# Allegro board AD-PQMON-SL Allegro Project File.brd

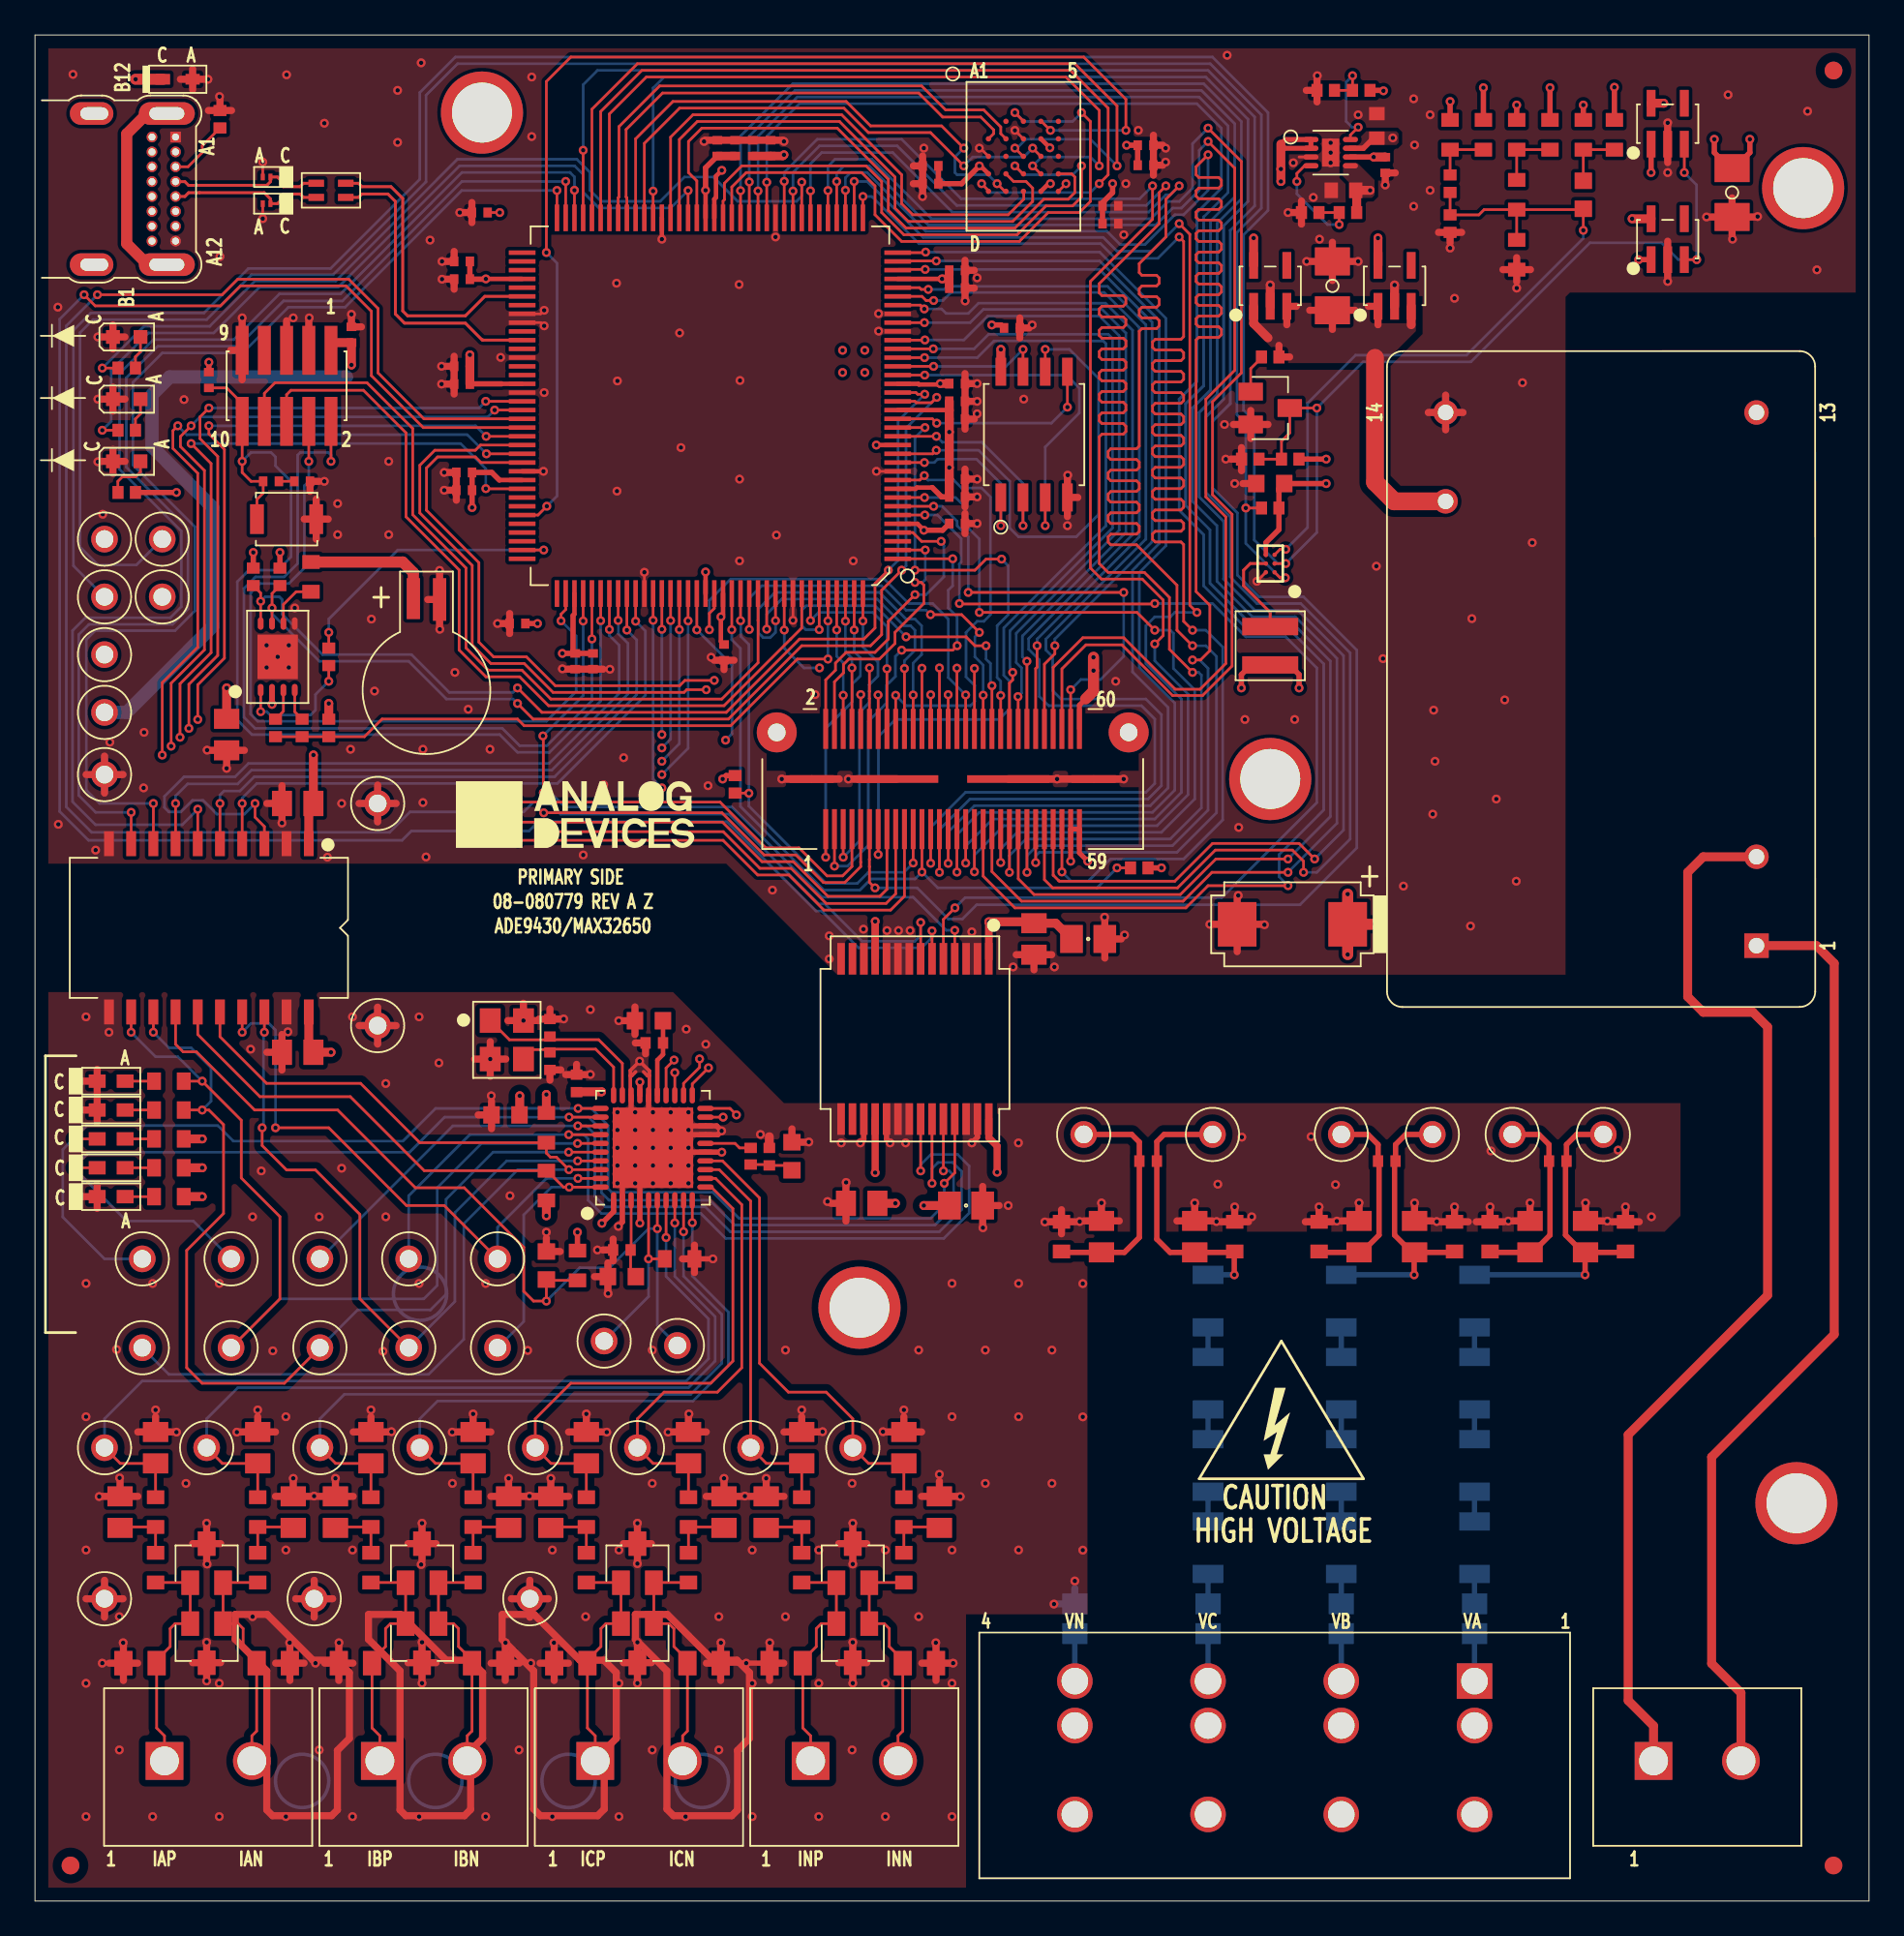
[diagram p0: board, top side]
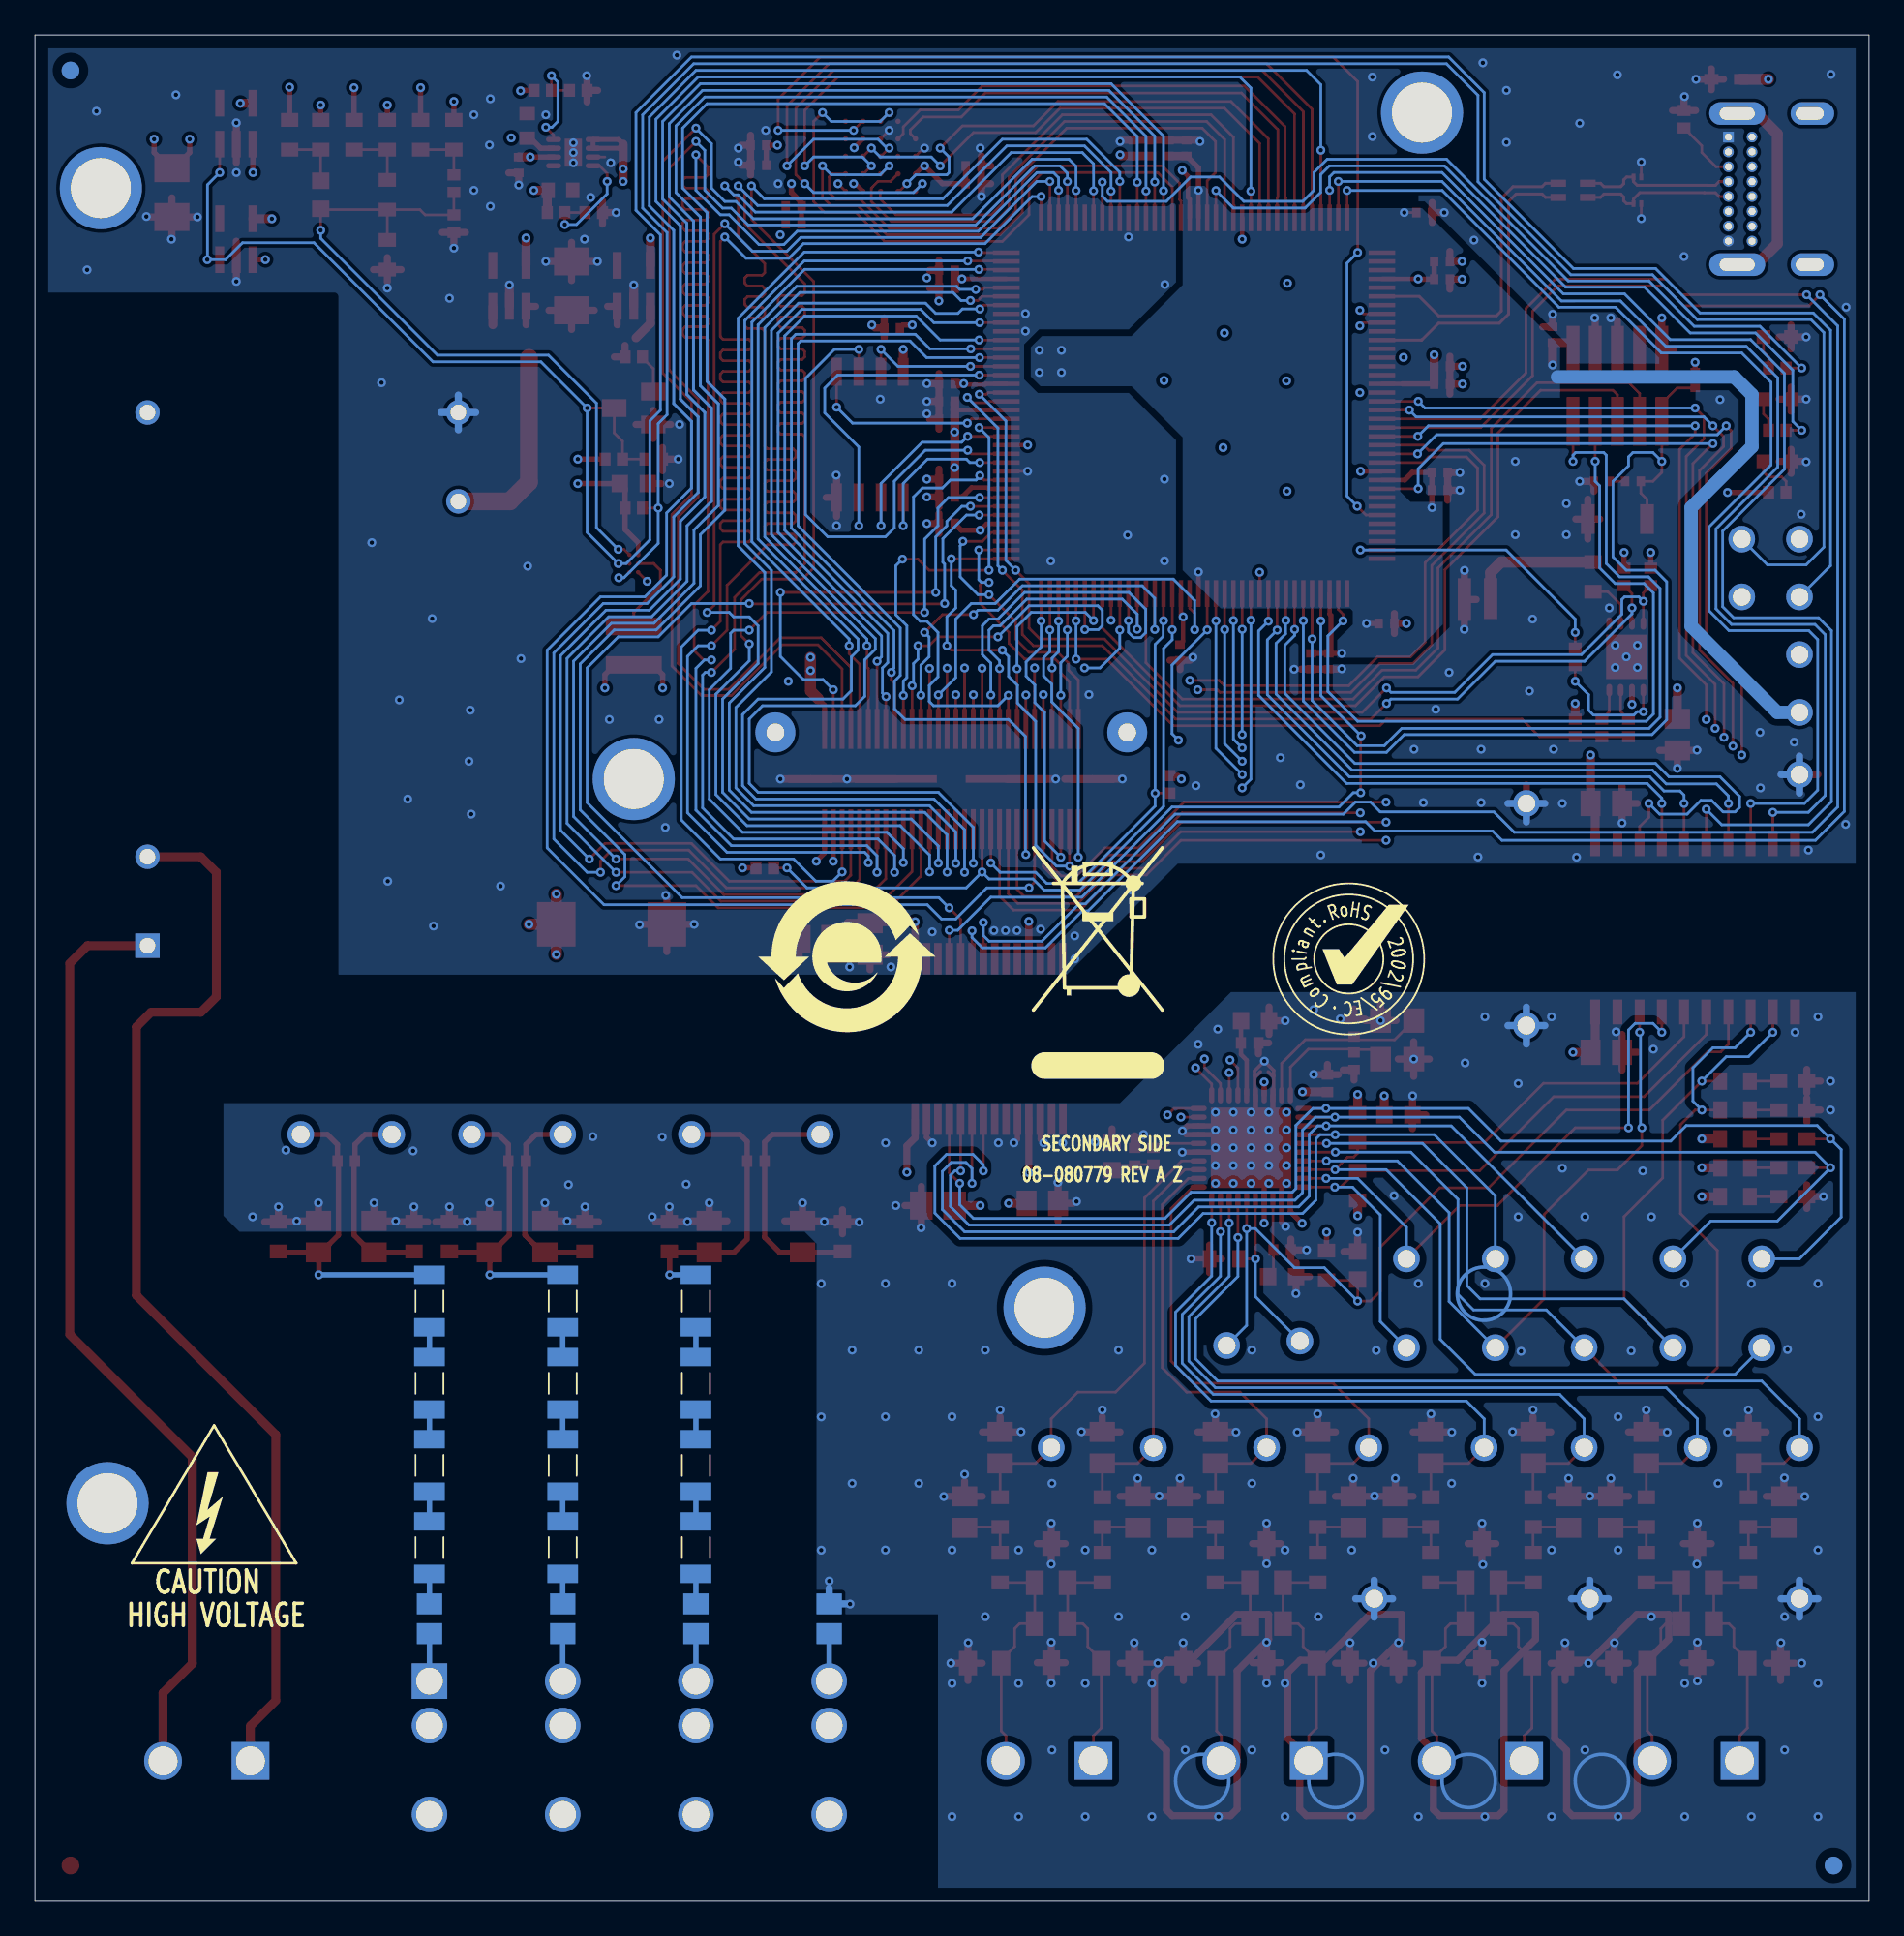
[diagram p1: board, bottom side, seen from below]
Outline 104.9 x 106.68 mm; copper layers: TOP, L2_GND, L3_PWR, BOTTOM. Coordinates in mm from the lower left corner of the outline.
Outline path: 0,106.68 0,0 104.9,0 104.9,106.68 0,106.68

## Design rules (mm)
constraint set DEFAULT: min track width 0.152
net group CLK_CS_MG: nets HYP_CLK HYP_CS0N
net group DP_USB_D_90OHM: nets USB_DN USB_DP
net group DP_USB_DP_CM_90OHM: nets USB_DN_CM USB_DP_CM
net group HYP_CLK: nets HYP_CLKN
net group RESET_CS_MG: nets HYP_RESET
net group SD_CARD: nets SDIO_CLK SDIO_CMD SDIO_DAT0 SDIO_DAT1 SDIO_DAT2 SDIO_DAT3

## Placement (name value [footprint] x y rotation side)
BT1  N/A  [BTMS621FE-FL11E]  22.39 69.22 180 top
C1  0.1uF  [C0805]  10.96 66.68 90 top
C2  0.1uF  [C0805]  57.14 55 90 top
C3  10uF  [C0805H60]  60.24 55 0 top
C4  0.1uF  [C0805]  15.03 62.75 0 top
C5  0.1uF  [C0805]  47.28 39.89 0 top
C6  0.1uF  [C0805]  15.03 48.52 0 top
C7  10uF  [C0805H60]  53.25 39.76 0 top
C8  470UF  [C7343H157]  71.92 55.84 180 top
C9  22uF  [C0603]  70.65 81.03 180 top
C10  22uF  [C1206H71]  74.21 92.34 90 top
C11  33pF  [C0603]  88.56 97.54 270 top
C12  22uF  [C1206H71]  97.07 97.67 270 top
C15  TBD0805  [C0805]  4.87 22.23 90 top
C16  TBD0805  [C0805]  14.77 22.23 270 top
C17  TBD0805  [C0805]  17.19 22.23 90 top
C18  TBD0805  [C0805]  27.09 22.23 270 top
C19  0.022UF  [C0805H55]  19.22 25.92 90 top
C20  0.022UF  [C0805H55]  25.06 25.92 270 top
C21  TBD0805  [C0805]  29.5 22.23 90 top
C22  TBD0805  [C0805]  39.41 22.23 270 top
C23  0.022UF  [C0805H55]  88.69 37.98 90 top
C24  0.022UF  [C0805H55]  31.54 25.92 90 top
C25  0.022UF  [C0805H55]  37.38 25.92 270 top
C26  TBD0805  [C0805]  41.82 22.23 90 top
C27  0.022UF  [C0805H55]  85.51 37.98 90 top
C28  TBD0805  [C0805]  51.73 22.23 270 top
C29  0.022UF  [C0805H55]  6.9 25.92 90 top
C30  0.022UF  [C0805H55]  12.74 25.92 270 top
C31  0.022UF  [C0805H55]  43.86 25.92 90 top
C32  0.022UF  [C0805H55]  49.7 25.92 270 top
C33  0.022UF  [C0805H55]  78.91 37.98 90 top
C34  0.022UF  [C0805H55]  66.33 37.98 90 top
C35  0.022UF  [C0805H55]  75.73 37.98 90 top
C36  0.022UF  [C0805H55]  61 37.98 90 top
C37  18pF  [C0402]  29.45 48.01 270 top
C38  18pF  [C0402]  29.45 49.92 90 top
C39  1uF  [C0603]  29.25 36.33 90 top
C40  4.7uF  [C0603]  26.91 44.94 0 top
C41  4.7uF  [C0603]  43.3 42.58 270 top
C42  4.7uF  [C0603]  35.12 50.33 0 top
C43  4.7uF  [C0603]  33.57 35.7 0 top
C44  0.1uF  [C0402]  30.98 46.74 270 top
C45  0.1uF  [C0402]  42 42.55 270 top
C46  0.1uF  [C0402]  35.42 49.06 0 top
C47  0.1uF  [C0402]  33.57 37.22 0 top
C52  51pF  [C0402]  87.1 42.3 180 top
C54  51pF  [C0402]  77.32 42.3 180 top
C55  51pF  [C0402]  63.67 42.3 180 top
C62  1uF  [C0402]  39.03 100.21 270 top
C63  1uF  [C0402]  25.44 96.53 0 top
C64  1uF  [C0402]  24.55 81.67 0 top
C65  1uF  [C0402]  52.75 92.21 180 top
C66  0.01uF  [C0402]  40.05 100.21 270 top
C67  0.01uF  [C0402]  52.75 86.75 180 top
C68  0.01uF  [C0402]  24.55 80.65 0 top
C69  0.01uF  [C0402]  52.75 93.23 180 top
C70  0.01uF  [C0402]  24.42 92.72 180 top
C71  0.01uF  [C0402]  52.75 85.73 0 top
C72  0.01uF  [C0402]  52.75 81.29 0 top
C73  0.01uF  [C0402]  42.08 100.21 90 top
C74  1uF  [C0402]  52.75 84.72 0 top
C75  1uF  [C0402]  24.42 93.73 180 top
C76  1uF  [C0402]  41.06 100.21 90 top
C77  1uF  [C0402]  52.75 80.27 0 top
C78  1uF  [C0402]  24.42 87.74 180 top
C79  1uF  [C0402]  24.42 86.72 180 top
C80  1uF  [C0402]  52.75 78.75 0 top
C81  1uF  [C0402]  39.41 71.38 270 top
C82  0.01uF  [C0402]  30.9 70.87 270 top
C83  1uF  [C0402]  31.92 70.87 270 top
C84  1uF  [C0402]  51.22 99.2 0 top
C85  0.1UF  [C0402]  51.22 98.18 180 top
C86  0.1UF  [C0402]  61.51 95.89 0 top
C87  1uF  [C0402]  61.51 96.91 0 top
C88  0.1UF  [C0402]  63.52 99.23 180 top
C89  0.1UF  [C0402]  63.52 100.38 180 top
C96  0.1UF  [C0402]  55.88 89.93 0 top
C101  0.1UF  [C0402]  18.1 89.54 90 top
C123  1uF  [C0402]  77.23 99.25 270 top
C124  4.7uF  [C0603#2]  74.84 97.8 180 top
C125  4.7uF  [C0603#2]  76.75 101.48 90 top
C142  1uF  [C0402]  27.6 73.03 180 top
C180  0.1UF  [C0402]  13.5 81.16 180 top
D6  SESD0201X1UN-0020-09  [D0201]  13.25 98.56 180 top
D7  SESD0201X1UN-0020-09  [D0201]  13.25 97.04 180 top
D10  1N4148X-TP  [SOD523_B]  8.17 104.15 0 top
DS1  LG L29K-G2J1-24-Z  [LED0603-2]  5.25 82.3 0 top
DS2  LG L29K-G2J1-24-Z  [LED0603-2]  5.25 85.86 0 top
DS3  LG L29K-G2J1-24-Z  [LED0603-2]  5.25 89.42 0 top
FB1  120OHM  [L0402]  40.93 42.58 90 top
L1  1500 OHMS  [L0805]  82.34 16.14 90 bottom
L2  1500 OHMS  [L0805]  74.72 16.14 90 bottom
L3  1500 OHMS  [L0805]  67.1 16.14 90 bottom
L4  1500 OHMS  [L0805]  59.48 16.14 90 bottom
L5  1.2UH  [LSMSQ110H118]  70.65 71.76 270 top
L7  90OHMS AT 100MEGHZ  [L0805-4PH39]  16.93 97.8 180 top
LED1  APT1608LSECK/J3-PRV  [LED0603]  4.36 43.57 0 top
LED2  APT1608LSECK/J3-PRV  [LED0603]  4.36 46.87 0 top
LED3  APT1608LSECK/J3-PRV  [LED0603]  4.36 45.22 0 top
LED5  APT1608LZGCK  [LED0603]  4.36 40.27 0 top
LED6  APT1608LSECK/J3-PRV  [LED0603]  4.36 41.92 0 top
M1  IRM-03-3.3  [MIRM-03]  98.47 54.62 90 top
NOREF  -  [unnamed]  102.87 2.03 0 top
NOREF#2  -  [#2]  52.31 134.86 0 top
NOREF#3  -  [#2]  -50.76 -152.01 0 top
NOREF#4  -  [#2]  7.41 8.01 0 top
NOREF#5  -  [#2]  206.9 9.22 0 top
NOREF#6  -  [#2]  220.51 -1.26 0 top
NOREF#7  -  [#2]  -50.76 -152.01 0 top
NOREF#8  -  [unnamed]  102.87 104.65 0 top
NOREF#9  -  [#2]  -50.76 -152.01 0 top
NOREF#10  -  [#2]  104.9 0 90 top
NOREF#11  -  [unnamed]  100.75 22.74 0 top
NOREF#12  -  [#2]  104.9 0 90 top
NOREF#13  -  [#2]  20.61 -29.71 0 top
NOREF#14  -  [#2]  6.14 15.11 90 top
NOREF#15  -  [#2]  71.03 26.93 0 top
NOREF#16  -  [#2]  52.45 53.34 0 top
NOREF#17  -  [#2]  0 0 0 top
NOREF#18  -  [#2]  104.9 106.68 180 top
NOREF#19  -  [#2]  177.18 229.35 0 top
NOREF#20  -  [#2]  0 0 0 top
NOREF#21  -  [#2]  224.68 7.78 0 top
NOREF#22  -  [#2]  0 106.68 0 top
NOREF#23  -  [#2]  14.49 100.36 0 top
NOREF#24  -  [unnamed]  101.13 97.93 0 top
NOREF#25  -  [unnamed]  70.65 64.14 0 top
NOREF#26  -  [unnamed]  47.16 33.92 0 top
NOREF#27  -  [unnamed]  25.57 102.24 0 top
NOREF#28  -  [#2]  104.9 0 0 top
NOREF#29  -  [#2]  0 0 0 top
NOREF#30  -  [#2]  0 106.68 0 top
NOREF#31  -  [#2]  229.22 120.79 0 top
NOREF#32  -  [#2]  0 106.68 270 top
NOREF#33  -  [#2]  51.73 4.15 270 top
NOREF#34  -  [#2]  30.77 62.11 0 top
NOREF#35  -  [#2]  131.44 363.85 0 top
NOREF#36  -  [#2]  7.41 8.01 0 top
NOREF#37  -  [unnamed]  2.03 2.03 0 top
NOREF#38  -  [#2]  29.76 53.86 180 bottom
NOREF#39  -  [#2]  58.46 53.98 180 bottom
NOREF#40  -  [unnamed]  2.03 2.03 180 bottom
NOREF#41  -  [#2]  34.84 63.89 180 bottom
NOREF#42  -  [unnamed]  102.87 104.65 180 bottom
NOREF#43  -  [#2]  94.91 22.11 180 bottom
P1  FTSH-105-01-L-DV-K  [CNHDR2X5H245]  14.39 86.62 180 top
P2  QSH-030-01-L-D-A  [CNHDR2X30H202]  52.49 64.14 0 top
P3  TBP04R2-500-02BE  [CNCUITBP04R2-500-02]  7.41 8.01 0 top
P4  TBP04R2-500-02BE  [CNCUITBP04R2-500-02]  19.73 8.01 0 top
P5  TBP04R2-500-02BE  [CNCUITBP04R2-500-02]  32.04 8.01 0 top
P6  TBP04R2-500-02BE  [CNCUITBP04R2-500-02]  44.36 8.01 0 top
P7  TBP04R2-500-02BE  [CNCUITBP04R2-500-02]  92.58 8.01 0 top
P8  1720592  [CNPHOENIX1720592]  82.34 12.57 180 top
P10  2137160001  [CNMOLEX2137160001]  8.04 100.85 270 top
Q1  MMBD4148SE  [SOT23]  9.82 19.31 0 top
Q2  MMBD4148SE  [SOT23]  9.82 14.74 180 top
Q3  MMBD4148SE  [SOT23]  22.14 19.31 0 top
Q4  MMBD4148SE  [SOT23]  22.14 14.74 180 top
Q5  MMBD4148SE  [SOT23]  34.46 19.31 0 top
Q6  MMBD4148SE  [SOT23]  34.46 14.74 180 top
Q7  MMBD4148SE  [SOT23]  46.78 19.31 0 top
Q8  BSS138LT1G  [SOT23]  70.65 85.35 270 top
Q9  MMBD4148SE  [SOT23]  46.78 14.74 180 top
R1  5.1  [R0805]  6.01 13.6 180 top
R2  5.1  [R0805]  13.63 13.6 180 top
R3  5.1  [R0805]  18.33 13.6 180 top
R4  5.1  [R0805]  25.95 13.6 180 top
R5  0  [R0603]  19.22 19.06 90 top
R6  0  [R0603]  25.06 19.06 90 top
R7  1K  [R0603]  19.22 22.23 90 top
R8  1K  [R0603]  25.06 22.23 90 top
R9  249K  [R1206]  82.34 20.2 90 bottom
R10  5.1  [R0805]  30.65 13.6 180 top
R11  5.1  [R0805]  38.27 13.6 180 top
R12  249K  [R1206]  74.72 20.2 90 bottom
R13  249K  [R1206]  67.1 20.2 90 bottom
R14  0  [R0603]  31.54 19.06 90 top
R15  0  [R0603]  37.38 19.06 90 top
R16  1K  [R0603]  31.54 22.23 90 top
R17  1K  [R0603]  37.38 22.23 90 top
R18  249K  [R1206]  82.34 24.9 90 bottom
R19  5.1  [R0805]  42.97 13.6 180 top
R20  5.1  [R0805]  50.59 13.6 180 top
R21  0  [R0603]  6.9 19.06 90 top
R22  0  [R0603]  12.74 19.06 90 top
R23  0  [R0603]  43.86 19.06 90 top
R24  0  [R0603]  49.7 19.06 90 top
R25  1K  [R0603]  43.86 22.23 90 top
R26  1K  [R0603]  49.7 22.23 90 top
R27  249K  [R1206]  74.72 24.9 90 bottom
R28  249K  [R1206]  67.1 24.9 90 bottom
R29  1K  [R0603]  90.97 37.98 90 top
R30  249K  [R1206]  82.34 29.6 90 bottom
R31  249K  [R1206]  74.72 29.6 90 bottom
R32  1K  [R0603]  81.19 37.98 90 top
R33  1K  [R0603]  83.23 37.98 90 top
R34  249K  [R1206]  67.1 29.6 90 bottom
R35  1K  [R0603]  6.9 22.23 90 top
R36  1K  [R0603]  12.74 22.23 90 top
R37  249K  [R1206]  82.34 34.3 90 bottom
R38  249K  [R1206]  74.72 34.3 90 bottom
R39  249K  [R1206]  67.1 34.3 90 bottom
R40  1K  [R0603]  68.62 37.98 90 top
R41  1K  [R0603]  73.45 37.98 90 top
R42  1K  [R0603]  58.71 37.98 90 top
R43  10K  [R0603]  31.03 36.33 90 top
R44  1K  [R0603]  7.66 43.57 0 top
R45  1K  [R0603]  7.66 41.92 0 top
R46  1K  [R0603]  7.66 46.87 0 top
R47  1K  [R0603]  7.66 45.22 0 top
R48  28K  [R0402]  75.86 103.51 180 top
R49  23.2K  [R0402]  73.83 103.51 180 top
R50  1K  [R0603]  7.66 40.27 0 top
R51  115K  [R0402]  75.1 96.53 180 top
R52  44.2K  [R0402]  72.94 96.53 180 top
R53  4.7K  [R0402]  40.05 63.84 270 top
R54  10K  [R0603]  29.25 40.9 270 top
R55  4.7K  [R0402]  63.16 59.06 180 top
R56  620  [R0603]  15.79 75.7 90 top
R57  4.7K  [R0402]  12.49 75.7 270 top
R58  0  [R0402]  16.8 71.13 90 top
R59  0  [R0402]  15.28 67.06 270 top
R60  0  [R0402]  13.76 67.06 270 top
R61  4.7K  [R0402]  14.01 75.7 270 top
R62  4.7K  [R0402]  16.8 67.06 270 top
R63  10K  [R0402]  70.65 88.27 180 top
R64  100K  [R0402]  70.65 79.64 180 top
R65  47K  [R0402]  71.8 82.43 180 top
R66  47K  [R0402]  69.51 82.43 180 top
R67  0  [R0603]  80.94 100.97 270 top
R68  0  [R0603]  82.84 100.97 270 top
R69  20K  [R0402]  80.94 98.18 270 top
R70  3.57K  [R0402]  80.94 95.89 270 top
R71  0  [R0603]  84.75 100.97 270 top
R72  0  [R0603]  86.65 100.97 270 top
R73  100K  [R0603]  84.75 97.54 270 top
R74  100K  [R0603]  84.75 94.12 270 top
R75  0  [R0603]  88.56 100.97 270 top
R76  0  [R0603]  90.34 100.97 270 top
R77  866  [R0402]  5.25 80.53 180 top
R78  866  [R0402]  5.25 84.08 0 top
R79  866  [R0402]  5.25 87.64 0 top
R81  10K  [R0603]  36.87 36.71 180 top
R96  10K  [R0603]  29.25 44.2 90 top
R125  10K  [R0402]  9.95 86.95 270 top
R126  10  [R0402]  15.28 81.16 0 top
R157  5.1K  [R0402]  10.58 101.86 270 top
S1  B3U-1000P  [SWSML118W98H69]  14.39 79 0 top
TP1  WHT  [CNKEY5001TP]  21.38 31.63 0 top
TP2  WHT  [CNKEY5001TP]  26.46 36.71 0 top
TP3  WHT  [CNKEY5001TP]  6.14 31.63 0 top
TP4  WHT  [CNKEY5001TP]  26.46 31.63 0 top
TP5  WHT  [CNKEY5001TP]  16.3 36.71 0 top
TP6  WHT  [CNKEY5001TP]  36.74 31.76 0 top
TP7  WHT  [CNKEY5001TP]  11.22 31.63 0 top
TP8  WHT  [CNKEY5001TP]  11.22 36.71 0 top
TP9  WHT  [CNKEY5001TP]  16.3 31.63 0 top
TP10  WHT  [CNKEY5001TP]  6.14 36.71 0 top
TP11  WHT  [CNKEY5001TP]  3.98 77.86 0 top
TP12  WHT  [CNKEY5001TP]  7.28 77.86 0 top
TP13  WHT  [CNKEY5001TP]  3.98 67.95 0 top
TP14  WHT  [CNKEY5001TP]  3.98 64.4 180 top
TP15  WHT  [CNKEY5001TP]  3.98 71.26 0 top
TP16  WHT  [CNKEY5001TP]  19.6 62.75 0 top
TP17  WHT  [CNKEY5001TP]  3.98 74.56 0 top
TP18  WHT  [CNKEY5001TP]  7.28 74.56 0 top
TP21  WHT  [CNKEY5001TP]  19.6 50.05 0 top
TP22  WHT  [CNKEY5001TP]  3.98 17.28 0 top
TP25  WHT  [CNKEY5001TP]  22.01 25.92 0 top
TP26  WHT  [CNKEY5001TP]  16.3 25.92 0 top
TP27  WHT  [CNKEY5001TP]  28.3 17.28 0 top
TP28  WHT  [CNKEY5001TP]  15.97 17.28 0 top
TP29  WHT  [CNKEY5001TP]  34.46 25.92 0 top
TP30  WHT  [CNKEY5001TP]  28.62 25.92 0 top
TP39  WHT  [CNKEY5001TP]  46.78 25.92 0 top
TP41  WHT  [CNKEY5001TP]  40.93 25.92 0 top
TP43  WHT  [CNKEY5001TP]  9.82 25.92 0 top
TP45  WHT  [CNKEY5001TP]  3.98 25.92 0 top
TP47  WHT  [CNKEY5001TP]  21.38 36.71 0 top
TP49  WHT  [CNKEY5001TP]  32.55 32.01 0 top
TP53  WHT  [CNKEY5001TP]  67.35 43.82 180 top
TP54  WHT  [CNKEY5001TP]  59.98 43.82 180 top
TP55  WHT  [CNKEY5001TP]  79.92 43.82 180 top
TP56  WHT  [CNKEY5001TP]  74.72 43.82 180 top
TP57  WHT  [CNKEY5001TP]  89.7 43.82 180 top
TP58  WHT  [CNKEY5001TP]  84.5 43.82 180 top
U1  ADE9430ACPZ  [QFN40_6X6_PAD4_6X4_6]  35.35 43.06 0 top
U2  MAX32650GCE+  [QFP144-4]  38.61 85.49 90 top
U3  MAX31343ETAY+T  [DFN8_3X4_PAD2_3X2_7]  13.88 71.13 0 top
U4  ADUM6424ABRNZ3  [SO28]  50.33 49.28 180 top
U5  ADUM4152BRIZ  [SO20WBH104]  9.95 55.63 180 top
U6  LTC3306  [WLCSP6H26]  70.65 76.46 90 top
U7  MAX40203AUK+  [SOT23-5L]  77.76 92.34 0 top
U8  MAX40203AUK+  [SOT23-5L]  70.65 92.34 0 top
U9  MAX40203AUK+  [SOT23-5L]  93.39 101.61 0 top
U10  S80KS5122GABHM020  [BGA24_8X6]  56.54 99.74 270 top
U11  MX25U6432FM2I02  [SOP8_A]  57.15 83.83 0 top
U12  MAX40203AUK+  [SOT23-5L]  93.39 95 0 top
U17  ADP225ACPZ  [QFN8_2X2_PAD1_6X1]  74.11 99.95 270 top
X2  24.576MEGHZ  [YSML126W98H31]  26.99 49.23 270 top

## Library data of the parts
BT1 = BAT: User Part Number: UPN; alternate symbols: (BTMS621FE-FL11E); part number: BAT_SM-N/A,3V,E017113,BTMS621FE-FL11E
C1 C2 C4-C6 = CAP: User Part Number: UPN; Tolerance: 5; alternate symbols: (C0805); part number: CAP_SM-0.1UF,50V,5,E031467,C0805; tolerance: 5
C3 C7 = CAP: Tolerance: 10; User Part Number: UPN; alternate symbols: (C0805H60); part number: CAP_SM-10UF,25V,10,E014704,C0805H60; tolerance: 10
C8 = CAPP: Tolerance: 20; User Part Number: UPN; alternate symbols: (C7343H157); part number: CAPP_SM-470UF,6.3V,20,E046064,C7343H157; tolerance: 20
C9 = CAP: User Part Number: UPN; Tolerance: 20; alternate symbols: (C0603); part number: CAP_SM-22UF,6.3V,20,E021512,C0603; tolerance: 20
C10 C12 = CAP: Tolerance: 20; User Part Number: UPN; alternate symbols: (C1206H71); part number: CAP_SM-22UF,6.3V,20,E042072,C1206H71; tolerance: 20
C11 = CAP: User Part Number: UPN; Tolerance: 5; alternate symbols: (C0603); part number: CAP_SM-33PF,50V,5,E000396,C0603; tolerance: 5
C15-C18 C21 C22 C26 C28 = CAP: User Part Number: UPN; alternate symbols: (C0805); part number: CAP_SM-TBD0805,TBD0805,TBD0805,E000383,C0805
C19 C20 C23-C25 C27 C29-C36 = CAP: User Part Number: UPN; Tolerance: 5; alternate symbols: (C0805H55); part number: CAP_SM-0.022UF,50V,5,E047690,C0805H55; tolerance: 5
C37 C38 = CAP: User Part Number: UPN; Tolerance: 5; alternate symbols: (C0402); part number: CAP_SM-18PF,50V,5,E007476,C0402; tolerance: 5
C39 = CAP: User Part Number: UPN; Tolerance: 10; alternate symbols: (C0603); part number: CAP_SM-1UF,16V,10,E020596,C0603; tolerance: 10
C40-C43 = CAP: User Part Number: UPN; Tolerance: 10; alternate symbols: (C0603); part number: CAP_SM-4.7UF,10V,10,E025322,C0603; tolerance: 10
C44-C47 = CAP: User Part Number: UPN; Tolerance: 10; alternate symbols: (C0402); part number: CAP_SM-0.1UF,25V,10,E025708,C0402; tolerance: 10
C52 C54 C55 = CAP: User Part Number: UPN; Tolerance: 5; alternate symbols: (C0402); part number: CAP_SM-51PF,50V,5,E029660,C0402; tolerance: 5
C62-C65 C74-C81 C83 C84 C87 C123 C142 = CAP: User Part Number: UPN; Tolerance: 10; alternate symbols: (C0402L); part number: CAP_SM-1UF,16V,10,E019219,C0402; tolerance: 10
C66-C73 C82 = CAP: User Part Number: UPN; Tolerance: 10; alternate symbols: (C0402L); part number: CAP_SM-0.01UF,100V,10,E032295,C0402; tolerance: 10
C85 C86 C88 C89 C96 C101 C180 = CAP: User Part Number: UPN; Tolerance: 10; alternate symbols: (C0402L); part number: CAP_SM-0.1UF,50V,10,E048331,C0402; tolerance: 10
C124 C125 = CAP: User Part Number: UPN; Tolerance: 10; alternate symbols: (C0603L); part number: CAP_SM-4.7UF,10V,10,E030749,C0603; tolerance: 10
D6 D7 = DIO: Tolerance: N/A; User Part Number: UPN; alternate symbols: (D0201); part number: DIO_SM-SESD0201X1UN-0020-09,9V,N/A,E022225,D0201; tolerance: N/A
D10 = DIO: Tolerance: N/A; User Part Number: UPN; alternate symbols: (SOD523_B); part number: DIO_SM-1N4148X-TP,75V,N/A,E039538,SOD523_B; tolerance: N/A
DS1-DS3 = DIOLED: Tolerance: N/A; User Part Number: UPN; alternate symbols: (LED0603-2); part number: DIOLED_SM-LG L29K-G2J1-24-Z,N/A,N/A,E010948,LED0603-2; tolerance: N/A
FB1 = FERRITE: User Part Number: UPN; Tolerance: 25; alternate symbols: (L0402); part number: FERRITE_SM-120OHM,25,E038542,L0402; tolerance: 25
L1-L4 = FERRITE: User Part Number: UPN; Tolerance: 25; alternate symbols: (L0805); part number: FERRITE_SM-1500 OHMS,25,E008092,L0805; tolerance: 25
L5 = IND_V10: Tolerance: 20; User Part Number: UPN; alternate symbols: (LSMSQ110H118); part number: IND_V10_SM-1.2UH,20,E061966,LSMSQ110H118; tolerance: 20
L7 = CHOKE4P: User Part Number: UPN; Tolerance: 25; alternate symbols: (L0805-4PH39); part number: CHOKE4P_SM-90OHMS AT 100MEGHZ,25,E027226,L0805-4PH39; tolerance: 25
LED1-LED3 LED6 = DIOLED: Tolerance: N/A; User Part Number: UPN; alternate symbols: (LED0603); part number: DIOLED_SM-APT1608LSECK/J3-PRV,1.8V,N/A,E030191,LED0603; tolerance: N/A
LED5 = DIOLED: Tolerance: N/A; User Part Number: UPN; alternate symbols: (LED0603); part number: DIOLED_SM-APT1608LZGCK,2.65V,N/A,E027397,LED0603; tolerance: N/A
M1 = MODIRM_03: User Part Number: UPN; Tolerance: N/A; alternate symbols: (MIRM-03); part number: MODIRM_03_TH-IRM-03-3.3,E064109,MIRM-03; tolerance: N/A
P1 = CN10P_ODD_EVEN: Tolerance: N/A; User Part Number: UPN; alternate symbols: (CNHDR2X5H245); part number: CN10P_ODD_EVEN_SM-FTSH-105-01-L-DV-K,E023407,CNHDR2X5H245; tolerance: N/A
P2 = CN60P_ODD_EVEN_4GND: User Part Number: UPN; Tolerance: N/A; alternate symbols: (CNHDR2X30H202); part number: CN60P_ODD_EVEN_4GND_SM-QSH-030-01-L-D-A,E014016,CNHDR2X30H202; tolerance: N/A
P3-P7 = CN2P: User Part Number: UPN; Tolerance: N/A; alternate symbols: (CNCUITBP04R2-500-02); part number: CN2P_TH-TBP04R2-500-02BE,E060556,CNCUITBP04R2-500-02; tolerance: N/A
P8 = CN4P_ABC: User Part Number: UPN; Tolerance: N/A; alternate symbols: (CNPHOENIX1720592); part number: CN4P_ABC_TH-1720592,E054826,CNPHOENIX1720592; tolerance: N/A
P10 = CN16PAB_4GND: Tolerance: N/A; User Part Number: UPN; alternate symbols: (CNMOLEX2137160001); part number: CN16PAB_4GND_TH-2137160001,E052752,CNMOLEX2137160001; tolerance: N/A
Q1-Q7 Q9 = DIOBAV99LT1: User Part Number: UPN; Tolerance: N/A; alternate symbols: (SOT23); part number: DIOBAV99LT1_SM-MMBD4148SE,100V,N/A,E007870,SOT23; tolerance: N/A
Q8 = TRANNMOSFET_V8: User Part Number: UPN; Tolerance: N/A; alternate symbols: (SOT23); part number: TRANNMOSFET_V8_SM-BSS138LT1G,E018770,SOT23; tolerance: N/A
R1-R4 R10 R11 R19 R20 = RES: User Part Number: UPN; Tolerance: 5; alternate symbols: (R0805); part number: RES_SM-5.1,E014529,1/8W,5,R0805; tolerance: 5
R5 R6 R14 R15 R21-R24 = RESJMPRSHRT: User Part Number: UPN; Tolerance: JUMPER; alternate symbols: (R0603); part number: RESJMPRSHRT_SM-0,E004447,1/10W,JUMPER,R0603; tolerance: JUMPER
R7 R8 R16 R17 R25 R26 R29 R32 R33 R35 R36 R40-R42 R44-R47 R50 = RES: User Part Number: UPN; Tolerance: 0.1; alternate symbols: (R0603); part number: RES_SM-1K,E020747,1/10W,0.1,R0603; tolerance: 0.1
R9 R12 R13 R18 R27 R28 R30 R31 R34 R37-R39 = RES: User Part Number: UPN; Tolerance: 0.1; alternate symbols: (R1206); part number: RES_SM-249K,E015146,1/4W,0.1,R1206; tolerance: 0.1
R43 R54 R81 R96 = RES: User Part Number: UPN; Tolerance: 5; alternate symbols: (R0603); part number: RES_SM-10K,E028377,1/10W,5,R0603; tolerance: 5
R48 = RES: User Part Number: UPN; Tolerance: 1; alternate symbols: (R0402); part number: RES_SM-28K,E010020,1/10W,1,R0402; tolerance: 1
R49 = RES: User Part Number: UPN; Tolerance: 1; alternate symbols: (R0402); part number: RES_SM-23.2K,E036030,1/10W,1,R0402; tolerance: 1
R51 = RES: User Part Number: UPN; Tolerance: 1; alternate symbols: (R0402); part number: RES_SM-115K,E025179,1/10W,1,R0402; tolerance: 1
R52 = RES: User Part Number: UPN; Tolerance: 1; alternate symbols: (R0402); part number: RES_SM-44.2K,E023712,1/10W,1,R0402; tolerance: 1
R53 R55 R57 R61 R62 = RES: User Part Number: UPN; Tolerance: 5; alternate symbols: (R0402); part number: RES_SM-4.7K,E048466,1/16W,5,R0402; tolerance: 5
R56 = RES: User Part Number: UPN; Tolerance: 1; alternate symbols: (R0603); part number: RES_SM-620,E033969,1/10W,1,R0603; tolerance: 1
R58-R60 = RES: User Part Number: UPN; Tolerance: JUMPER; alternate symbols: (R0402); part number: RES_SM-0,E003438,1/10W,JUMPER,R0402; tolerance: JUMPER
R63 = RES: User Part Number: UPN; Tolerance: 1; alternate symbols: (R0402); part number: RES_SM-10K,E060779,1/16W,1,R0402; tolerance: 1
R64 = RES: User Part Number: UPN; Tolerance: 5; alternate symbols: (R0402); part number: RES_SM-100K,E027220,1/16W,5,R0402; tolerance: 5
R65 R66 = RES: User Part Number: UPN; Tolerance: 0.5; alternate symbols: (R0402); part number: RES_SM-47K,E031653,1/16W,0.5,R0402; tolerance: 0.5
R67 R68 R71 R72 R75 R76 = RES: User Part Number: UPN; Tolerance: JUMPER; alternate symbols: (R0603); part number: RES_SM-0,E034483,1/10W,JUMPER,R0603; tolerance: JUMPER
R69 = RES: User Part Number: UPN; Tolerance: 1; alternate symbols: (R0402); part number: RES_SM-20K,E061761,1/16W,1,R0402; tolerance: 1
R70 = RES: User Part Number: UPN; Tolerance: 1; alternate symbols: (R0402); part number: RES_SM-3.57K,E007344,1/10W,1,R0402; tolerance: 1
R73 R74 = RES: User Part Number: UPN; Tolerance: 0.5; alternate symbols: (R0603); part number: RES_SM-100K,E012705,1/10W,0.5,R0603; tolerance: 0.5
R77-R79 = RES: User Part Number: UPN; Tolerance: 1; alternate symbols: (R0402); part number: RES_SM-866,E015598,1/10W,1,R0402; tolerance: 1
R125 = RES: User Part Number: UPN; Tolerance: 1; alternate symbols: (R0402L); part number: RES_SM-10K,E003751,1/10W,1,R0402; tolerance: 1
R126 = RES: User Part Number: UPN; Tolerance: 1; alternate symbols: (R0402L); part number: RES_SM-10,E003768,1/10W,1,R0402; tolerance: 1
R157 = RES: User Part Number: UPN; Tolerance: 0.1; alternate symbols: (R0402); part number: RES_SM-5.1K,E010267,1/16W,0.1,R0402; tolerance: 0.1
S1 = SWSPST2PIN_V2: Tolerance: N/A; User Part Number: UPN; alternate symbols: (SWSML118W98H69); part number: SWSPST2PIN_V2_SM-B3U-1000P,E016303,SWSML118W98H69; tolerance: N/A
TP1-TP18 TP21 TP22 TP25-TP30 TP39 TP41 TP43 TP45 TP47 TP49 TP53-TP58 = CNTP1P: Tolerance: N/A; User Part Number: UPN; alternate symbols: (CNKEY5001TP); part number: CNTP1P_TH-WHT,E006153,CNKEY5001TP; tolerance: N/A
U1 = ADE9430: User Part Number: UPN; Tolerance: N/A; alternate symbols: (QFN40_6X6_PAD4_6X4_6); part number: ADE9430_SM-ADE9430ACPZ,E050046,QFN40_6X6_PAD4_6X4_6; tolerance: N/A
U2 = ADMAX3265X: Tolerance: N/A; User Part Number: UPN; alternate symbols: (QFP144-4); part number: ADMAX3265X_SM-MAX32650GCE+,E058988,QFP144-4; tolerance: N/A
U3 = ADMAX31343: User Part Number: UPN; Tolerance: N/A; alternate symbols: (DFN8_3X4_PAD2_3X2_7); part number: ADMAX31343_SM-MAX31343ETAY+T,E059805,DFN8_3X4_PAD2_3X2_7; tolerance: N/A
U4 = ADUM6424A: User Part Number: UPN; Tolerance: N/A; alternate symbols: (SO28); part number: ADUM6424A_SM-ADUM6424ABRNZ3,E064108,SO28; tolerance: N/A
U5 = ADUM4152: Tolerance: N/A; User Part Number: UPN; alternate symbols: (SO20WBH104); part number: ADUM4152_SM-ADUM4152BRIZ,E033349,SO20WBH104; tolerance: N/A
U6 = ADLTC3306: Tolerance: N/A; User Part Number: UPN; alternate symbols: (WLCSP6H26); part number: ADLTC3306_SM-LTC3306,E041728,WLCSP6H26; tolerance: N/A
U7-U9 U12 = ADMAX40203: User Part Number: UPN; Tolerance: N/A; alternate symbols: (SOT23-5L); part number: ADMAX40203_SM-MAX40203AUK+,E059461,SOT23-5L; tolerance: N/A
U10 = ICS80KS5122: Tolerance: N/A; User Part Number: UPN; alternate symbols: (BGA24_8X6_PB); part number: ICS80KS5122_SM-S80KS5122GABHM020,E060311,BGA24_8X6; tolerance: N/A
U11 = ICMX25U6432F_V2: User Part Number: UPN; Tolerance: N/A; alternate symbols: (SOP8_A); part number: ICMX25U6432F_V2_SM-MX25U6432FM2I02,E060310,SOP8_A; tolerance: N/A
U17 = ADP22X: User Part Number: UPN; Tolerance: N/A; alternate symbols: (QFN8_2X2_PAD1_6X1); part number: ADP22X_SM-ADP225ACPZ,E016555,QFN8_2X2_PAD1_6X1; tolerance: N/A
X2 = XTAL4PIN_V5: Tolerance: +/-20PPM; User Part Number: UPN; alternate symbols: (YSML126W98H31); part number: XTAL4PIN_V5_SM-24.576MEGHZ,E041028,YSML126W98H31; tolerance: +/-20PPM

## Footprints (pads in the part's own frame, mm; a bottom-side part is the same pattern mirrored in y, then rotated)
BGA24_8X6
  round 0.305 smd: A2(-2,-1) A3(-2,0) A4(-2,1) A5(-2,2) B1(-1,-2) B2(-1,-1) B3(-1,0) B4(-1,1) B5(-1,2) C1(0,-2) C2(0,-1) C3(0,0) C4(0,1) C5(0,2) D1(1,-2) D2(1,-1) D3(1,0) D4(1,1) D5(1,2) E1(2,-2) E2(2,-1) E3(2,0) E4(2,1) E5(2,2)
BTMS621FE-FL11E
  rect 0.762x2.438 smd: N(-0.75,-5.181)
  rect 0.762x2.337 smd: P(0.75,-5.232)
C0402
  rect 0.483x0.559 smd: 1(-0.45,0) 2(0.45,0)
C0603
  rect 0.94x0.991 smd: 1(-0.8,0) 2(0.8,0)
C0603#2
  rect 0.762x0.889 smd: 1(-0.7,0) 2(0.7,0)
C0805
  rect 1.143x1.448 smd: 1(-0.9,0) 2(0.9,0)
C0805H55
  rect 1.143x1.448 smd: 1(-0.9,0) 2(0.9,0)
C0805H60
  rect 1.295x1.6 smd: 1(-0.953,0) 2(0.953,0)
C1206H71
  rect 1.6x2.007 smd: 1(-1.397,0) 2(1.397,0)
C7343H157
  rect 2.21x2.54 smd: N(3.16,0) P(-3.16,0)
CNCUITBP04R2-500-02
  rect 2.159x2.159 hole 1.651: 1(0,0)
  round 2.159 hole 1.651: 2(5,0)
CNHDR2X5H245
  rect 0.737x2.794 smd: 1(-2.54,-2.032) 2(-2.54,2.032) 3(-1.27,-2.032) 4(-1.27,2.032) 5(0,-2.032) 6(0,2.032) 7(1.27,-2.032) 8(1.27,2.032) 9(2.54,-2.032) 10(2.54,2.032)
CNHDR2X30H202
  round 2.286 hole 1.016 unplated: (-10.063,2.667) (10.063,2.667)
  rect 0.279x2.286 smd: 1(-7.264,-2.865) 2(-7.264,2.865) 3(-6.764,-2.865) 4(-6.764,2.865) 5(-6.264,-2.865) 6(-6.264,2.865) 7(-5.763,-2.865) 8(-5.763,2.865) 9(-5.263,-2.865) 10(-5.263,2.865) 11(-4.763,-2.865) 12(-4.763,2.865) 13(-4.262,-2.865) 14(-4.262,2.865) 15(-3.762,-2.865) 16(-3.762,2.865) 17(-3.261,-2.865) 18(-3.261,2.865) 19(-2.761,-2.865) 20(-2.761,2.865) 21(-2.261,-2.865) 22(-2.261,2.865) 23(-1.76,-2.865) 24(-1.76,2.865) 25(-1.26,-2.865) 26(-1.26,2.865) 27(-0.759,-2.865) 28(-0.759,2.865) 29(-0.259,-2.865) 30(-0.259,2.865) 31(0.241,-2.865) 32(0.241,2.865) 33(0.742,-2.865) 34(0.742,2.865) 35(1.242,-2.865) 36(1.242,2.865) 37(1.742,-2.865) 38(1.742,2.865) 39(2.243,-2.865) 40(2.243,2.865) 41(2.743,-2.865) 42(2.743,2.865) 43(3.244,-2.865) 44(3.244,2.865) 45(3.744,-2.865) 46(3.744,2.865) 47(4.244,-2.865) 48(4.244,2.865) 49(4.745,-2.865) 50(4.745,2.865) 51(5.245,-2.865) 52(5.245,2.865) 53(5.745,-2.865) 54(5.745,2.865) 55(6.246,-2.865) 56(6.246,2.865) 57(6.746,-2.865) 58(6.746,2.865) 59(7.247,-2.865) 60(7.247,2.865)
  rect 2.54x0.432 smd: PAD1(-8.065,0) PAD4(8.065,0)
  rect 4.699x0.432 smd: PAD2(-3.175,0) PAD3(3.175,0)
CNKEY5001TP
  round 1.524 hole 1.016: 1(0,0)
CNMOLEX2137160001
  rect 0.61x0.61 hole 0.406: A1(0,0)
  round 0.61 hole 0.406: A4(0.85,0) A5(1.7,0) A6(2.55,0) A7(3.4,0) A8(4.25,0) A9(5.1,0) A12(5.95,0) B1(5.95,-1.35) B4(5.1,-1.35) B5(4.25,-1.35) B6(3.4,-1.35) B7(2.55,-1.35) B8(1.7,-1.35) B9(0.85,-1.35) B12(0,-1.35)
  oval 1.295x3.2 hole 0.711x2.007: GND1(-1.345,-0.5) GND2(7.295,-0.5)
  oval 1.295x2.489 hole 0.711x1.6: GND3(-1.345,-4.65) GND4(7.295,-4.65)
CNPHOENIX1720592
  rect 2.032x2.032 hole 1.524: 1A(0,0)
  round 2.032 hole 1.524: 1B(0,2.54) 1C(0,7.62) 2A(7.62,0) 2B(7.62,2.54) 2C(7.62,7.62) 3A(15.24,0) 3B(15.24,2.54) 3C(15.24,7.62) 4A(22.86,0) 4B(22.86,2.54) 4C(22.86,7.62)
D0201
  rect 0.229x0.381 smd: A(0.22,0) C(-0.22,0)
DFN8_3X4_PAD2_3X2_7
  oval 0.33x0.711 smd: 1(-0.975,-1.906) 2(-0.325,-1.906) 3(0.325,-1.906) 4(0.975,-1.906) 5(0.975,1.906) 6(0.325,1.906) 7(-0.325,1.906) 8(-0.975,1.906)
  rect 2.311x2.54 smd: PAD(0,0)
L0402
  rect 0.584x0.711 smd: 1(-0.475,0) 2(0.475,0)
L0805
  rect 1.194x1.448 smd: 1(-0.85,0) 2(0.85,0)
L0805-4PH39
  rect 0.889x0.406 smd: 1(-0.845,-0.403) 2(0.845,-0.403) 3(0.845,0.403) 4(-0.845,0.403)
LED0603
  rect 0.965x0.762 smd: A(0.8,0) C(-0.8,0)
LED0603-2
  rect 0.787x0.787 smd: A(0.787,0) C(-0.787,0)
LSMSQ110H118
  rect 0.991x3.2 smd: 1(-1.095,0) 2(1.095,0)
MIRM-03
  rect 1.397x1.397 hole 0.889: 1(0,0)
  round 1.397 hole 0.889: 3(5.08,0) 13(30.48,0) 14(30.48,17.78) 16(25.4,17.78)
QFN8_2X2_PAD1_6X1
  oval 0.305x0.864 smd: 1(-0.75,-1.13) 2(-0.25,-1.13) 3(0.25,-1.13) 4(0.75,-1.13) 5(0.75,1.13) 6(0.25,1.13) 7(-0.25,1.13) 8(-0.75,1.13)
  rect 1.6x0.991 smd: PAD(0,0)
QFN40_6X6_PAD4_6X4_6
  oval 0.305x0.94 smd: 1(-2.25,-3.005) 2(-1.75,-3.005) 3(-1.25,-3.005) 4(-0.75,-3.005) 5(-0.25,-3.005) 6(0.25,-3.005) 7(0.75,-3.005) 8(1.25,-3.005) 9(1.75,-3.005) 10(2.25,-3.005) 21(2.25,3.005) 22(1.75,3.005) 23(1.25,3.005) 24(0.75,3.005) 25(0.25,3.005) 26(-0.25,3.005) 27(-0.75,3.005) 28(-1.25,3.005) 29(-1.75,3.005) 30(-2.25,3.005)
  oval 0.94x0.305 smd: 11(3.005,-2.25) 12(3.005,-1.75) 13(3.005,-1.25) 14(3.005,-0.75) 15(3.005,-0.25) 16(3.005,0.25) 17(3.005,0.75) 18(3.005,1.25) 19(3.005,1.75) 20(3.005,2.25) 31(-3.005,2.25) 32(-3.005,1.75) 33(-3.005,1.25) 34(-3.005,0.75) 35(-3.005,0.25) 36(-3.005,-0.25) 37(-3.005,-0.75) 38(-3.005,-1.25) 39(-3.005,-1.75) 40(-3.005,-2.25)
  rect 4.597x4.597 smd: PAD(0,0)
QFP144-4
  rect 0.254x1.524 smd: 1(-8.75,-10.74) 2(-8.25,-10.74) 3(-7.75,-10.74) 4(-7.25,-10.74) 5(-6.75,-10.74) 6(-6.25,-10.74) 7(-5.75,-10.74) 8(-5.25,-10.74) 9(-4.75,-10.74) 10(-4.25,-10.74) 11(-3.75,-10.74) 12(-3.25,-10.74) 13(-2.75,-10.74) 14(-2.25,-10.74) 15(-1.75,-10.74) 16(-1.25,-10.74) 17(-0.75,-10.74) 18(-0.25,-10.74) 19(0.25,-10.74) 20(0.75,-10.74) 21(1.25,-10.74) 22(1.75,-10.74) 23(2.25,-10.74) 24(2.75,-10.74) 25(3.25,-10.74) 26(3.75,-10.74) 27(4.25,-10.74) 28(4.75,-10.74) 29(5.25,-10.74) 30(5.75,-10.74) 31(6.25,-10.74) 32(6.75,-10.74) 33(7.25,-10.74) 34(7.75,-10.74) 35(8.25,-10.74) 36(8.75,-10.74) 73(8.75,10.74) 74(8.25,10.74) 75(7.75,10.74) 76(7.25,10.74) 77(6.75,10.74) 78(6.25,10.74) 79(5.75,10.74) 80(5.25,10.74) 81(4.75,10.74) 82(4.25,10.74) 83(3.75,10.74) 84(3.25,10.74) 85(2.75,10.74) 86(2.25,10.74) 87(1.75,10.74) 88(1.25,10.74) 89(0.75,10.74) 90(0.25,10.74) 91(-0.25,10.74) 92(-0.75,10.74) 93(-1.25,10.74) 94(-1.75,10.74) 95(-2.25,10.74) 96(-2.75,10.74) 97(-3.25,10.74) 98(-3.75,10.74) 99(-4.25,10.74) 100(-4.75,10.74) 101(-5.25,10.74) 102(-5.75,10.74) 103(-6.25,10.74) 104(-6.75,10.74) 105(-7.25,10.74) 106(-7.75,10.74) 107(-8.25,10.74) 108(-8.75,10.74)
  rect 1.524x0.254 smd: 37(10.74,-8.75) 38(10.74,-8.25) 39(10.74,-7.75) 40(10.74,-7.25) 41(10.74,-6.75) 42(10.74,-6.25) 43(10.74,-5.75) 44(10.74,-5.25) 45(10.74,-4.75) 46(10.74,-4.25) 47(10.74,-3.75) 48(10.74,-3.25) 49(10.74,-2.75) 50(10.74,-2.25) 51(10.74,-1.75) 52(10.74,-1.25) 53(10.74,-0.75) 54(10.74,-0.25) 55(10.74,0.25) 56(10.74,0.75) 57(10.74,1.25) 58(10.74,1.75) 59(10.74,2.25) 60(10.74,2.75) 61(10.74,3.25) 62(10.74,3.75) 63(10.74,4.25) 64(10.74,4.75) 65(10.74,5.25) 66(10.74,5.75) 67(10.74,6.25) 68(10.74,6.75) 69(10.74,7.25) 70(10.74,7.75) 71(10.74,8.25) 72(10.74,8.75) 109(-10.74,8.75) 110(-10.74,8.25) 111(-10.74,7.75) 112(-10.74,7.25) 113(-10.74,6.75) 114(-10.74,6.25) 115(-10.74,5.75) 116(-10.74,5.25) 117(-10.74,4.75) 118(-10.74,4.25) 119(-10.74,3.75) 120(-10.74,3.25) 121(-10.74,2.75) 122(-10.74,2.25) 123(-10.74,1.75) 124(-10.74,1.25) 125(-10.74,0.75) 126(-10.74,0.25) 127(-10.74,-0.25) 128(-10.74,-0.75) 129(-10.74,-1.25) 130(-10.74,-1.75) 131(-10.74,-2.25) 132(-10.74,-2.75) 133(-10.74,-3.25) 134(-10.74,-3.75) 135(-10.74,-4.25) 136(-10.74,-4.75) 137(-10.74,-5.25) 138(-10.74,-5.75) 139(-10.74,-6.25) 140(-10.74,-6.75) 141(-10.74,-7.25) 142(-10.74,-7.75) 143(-10.74,-8.25) 144(-10.74,-8.75)
R0402
  rect 0.635x0.737 smd: 1(-0.5,0) 2(0.5,0)
R0603
  rect 0.787x0.991 smd: 1(-0.85,0) 2(0.85,0)
R0805
  rect 1.041x1.397 smd: 1(-0.95,0) 2(0.95,0)
R1206
  rect 1.041x1.753 smd: 1(-1.5,0) 2(1.5,0)
SO20WBH104
  rect 0.559x1.422 smd: 1(-5.715,-4.81) 2(-4.445,-4.81) 3(-3.175,-4.81) 4(-1.905,-4.81) 5(-0.635,-4.81) 6(0.635,-4.81) 7(1.905,-4.81) 8(3.175,-4.81) 9(4.445,-4.81) 10(5.715,-4.81) 11(5.715,4.81) 12(4.445,4.81) 13(3.175,4.81) 14(1.905,4.81) 15(0.635,4.81) 16(-0.635,4.81) 17(-1.905,4.81) 18(-3.175,4.81) 19(-4.445,4.81) 20(-5.715,4.81)
SO28
  rect 0.432x1.803 smd: 1(-4.225,-4.582) 2(-3.575,-4.582) 3(-2.925,-4.582) 4(-2.275,-4.582) 5(-1.625,-4.582) 6(-0.975,-4.582) 7(-0.325,-4.582) 8(0.325,-4.582) 9(0.975,-4.582) 10(1.625,-4.582) 11(2.275,-4.582) 12(2.925,-4.582) 13(3.575,-4.582) 14(4.225,-4.582) 15(4.225,4.582) 16(3.575,4.582) 17(2.925,4.582) 18(2.275,4.582) 19(1.625,4.582) 20(0.975,4.582) 21(0.325,4.582) 22(-0.325,4.582) 23(-0.975,4.582) 24(-1.625,4.582) 25(-2.275,4.582) 26(-2.925,4.582) 27(-3.575,4.582) 28(-4.225,4.582)
SOD523_B
  rect 0.813x0.61 smd: A(0.85,0) C(-0.85,0)
SOP8_A
  rect 0.61x1.6 smd: 1(-1.905,-3.594) 2(-0.635,-3.594) 3(0.635,-3.594) 4(1.905,-3.594) 5(1.905,3.594) 6(0.635,3.594) 7(-0.635,3.594) 8(-1.905,3.594)
SOT23
  rect 1.016x1.397 smd: 1(-0.94,-1.118) 2(0.94,-1.118) 3(0,1.118)
SOT23-5L
  rect 0.508x1.524 smd: 1(-0.95,-1.17) 2(0,-1.17) 3(0.95,-1.17) 4(0.95,1.17) 5(-0.95,1.17)
SWSML118W98H69
  rect 0.787x1.702 smd: 1(-1.694,0) 2(1.694,0)
unnamed
  round 1.016 smd: (0,0)
WLCSP6H26
  round 0.254 smd: A1(-0.5,-0.25) A2(-0.5,0.25) B1(0,-0.25) B2(0,0.25) C1(0.5,-0.25) C2(0.5,0.25)
YSML126W98H31
  rect 1.397x1.194 smd: 1(-1.1,-0.95) 2(1.1,-0.95) 3(1.1,0.95) 4(-1.1,0.95)

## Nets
1V1: C78.1 C79.1 C80.1 C125.1 R48.1 TP15.1(N1) U2.5 U2.14 U2.88 U17.7
1V8: C62.2(N2) C63.2(N2) C64.2(N2) C65.2(N2) C66.2(N2) C67.2(N2) C68.2(N2) C69.2(N2) C82.1 C83.1 C84.2(N2) C85.1 C86.1 C87.1 C88.2(N2) C89.2(N2) C96.1 C101.1 C124.1 C142.1 P1.1 P2.60 R51.1 TP13.1(N1) U2.21 U2.33 U2.55 U2.99 U2.111 U2.126 U10.B4 U10.D1 U10.E4 U11.8 U17.5(VOUT2)
3V3: C1.2(N2) C2.2(N2) C3.1 C4.2(N2) C70.1 C71.1 C72.1 C73.1 C74.1 C75.1 C76.1 C77.1 C81.1 C123.1 P2.57 P2.59 R53.1 R55.1 R57.1 R61.1 R62.1 R67.1 R71.1 R75.1 R77.1 R125.1 U2.9 U2.18 U2.54 U2.76 U2.128 U3.2(VCC) U4.1 U4.11 U5.1 U7.5 U8.5 U9.5 U12.5 U17.1 U17.2 U17.6
3V3_USB: C12.1 L5.2(N2) R68.1 R72.1 R76.1 TP18.1(N1) U9.1(VDD) U12.1(VDD)
3V3_WALL: C10.1 M1.16 R63.1 U7.1(VDD) U7.3 U8.1(VDD) U8.3
+3V3_ADE: C5.2(N2) C6.2(N2) C7.1 C40.2(N2) C44.2(N2) R43.2(N2) R44.2(N2) R45.2(N2) R50.2(N2) R54.2(N2) R96.2(N2) U1.1 U1.27(VDD) U4.18 U4.28 U5.20
AVDDOUT: C42.2(N2) C46.2(N2) U1.25
DGND: BT1.N(N2) C1.1 C2.1 C3.2(N2) C4.1 C8.N(N2) C9.2(N2) C10.2(N2) C12.2(N2) C62.1 C63.1 C64.1 C65.1 C66.1 C67.1 C68.1 C69.1 C70.2(N2) C71.2(N2) C72.2(N2) C73.2(N2) C74.2(N2) C75.2(N2) C76.2(N2) C77.2(N2) C78.2(N2) C79.2(N2) C80.2(N2) C81.2(N2) C82.2(N2) C83.2(N2) C84.1 C85.2(N2) C86.2(N2) C87.2(N2) C88.1 C89.1 C96.2(N2) C101.2(N2) C123.2(N2) C124.2(N2) C125.2(N2) C142.2(N2) D6.A(P) D7.A(P) D10.A(P) DS1.C DS2.C DS3.C M1.14 P1.3 P1.5 P1.9 P2.PAD1 P2.PAD2 P2.PAD3 P2.PAD4 P10.A1 P10.A12 Q8.2(S) R49.2(N2) R52.2(N2) R66.2(N2) R70.2(N2) R74.2(N2) R126.2(N2) R157.1 S1.2(B) TP14.1(N1) TP16.1(N1) U2.11 U2.27 U2.29 U2.47 U2.60 U2.80 U2.81 U2.85 U2.89(VSS_9) U2.98 U2.119 U2.136 U3.5 U3.PAD U4.2 U4.3 U4.8 U4.9 U4.10 U4.12 U4.14 U5.2 U5.10 U6.A2 U7.2 U8.2 U9.2 U10.B3 U10.C1 U10.E5(VSSQ_2) U11.4 U12.2 U17.3 U17.PAD
DVDDOUT: C43.2(N2) C47.2(N2) U1.3
GND: C5.1 C6.1 C7.2(N2) C15.2(N2) C16.1 C17.2(N2) C18.1 C19.2(N2) C20.1 C21.2(N2) C22.1 C23.2(N2) C24.2(N2) C25.1 C26.2(N2) C27.2(N2) C28.1 C29.2(N2) C30.1 C31.2(N2) C32.1 C33.2(N2) C34.2(N2) C35.2(N2) C36.2(N2) C37.2(N2) C38.2(N2) C39.2(N2) C40.1 C41.1 C42.1 C43.1 C44.1 C45.1 C46.1 C47.1 L4.2(N2) LED2.C LED3.C LED5.C Q1.3 Q2.3 Q3.3 Q4.3 Q5.3 Q6.3 Q7.3 Q9.3 R1.2(N2) R2.1 R3.2(N2) R4.1 R10.2(N2) R11.1 R19.2(N2) R20.1 R29.2(N2) R32.2(N2) R33.2(N2) R40.2(N2) R41.2(N2) R42.2(N2) R81.1 TP21.1(N1) TP22.1(N1) TP27.1(N1) TP28.1(N1) U1.2 U1.4 U1.15 U1.17 U1.18 U1.26 U1.28 U1.PAD U4.15 U4.17 U4.19 U4.20(VSEL) U4.21 U4.26 U4.27 U5.11 U5.19 X2.2 X2.4
VBAT: BT1.P R56.2(N2)
ADIN1110_RESET: P2.24 U2.121
BTN_0: P2.7 U2.94
BTN_1: P2.9 U2.90
BTN_2: P2.11 U2.69
BTN_3: P2.13 U2.24
BTN_4: P2.15 U2.100
CF1_ADC: U2.93 U4.6
CF1_ADE: TP5.1(N1) U1.33 U4.23
CF2_ADC: U2.92 U4.7
CF2_ADE: TP47.1(N1) U1.34 U4.22
CF3_ADC: U2.71 U5.9(VOC)
CF3_ZX_ADE: R46.2(N2) TP7.1(N1) U1.35 U5.12
CF4_ADC: U2.72 U5.8
CF4_DREADY_ADE: R47.2(N2) TP9.1(N1) U1.36 U5.13
HYP_CLK: U2.65 U10.B2
HYP_CLKN: U2.64 U10.B1
HYP_CS0N: U2.52 U10.A3
HYP_D0: U2.53 U10.D3
HYP_D1: U2.58 U10.D2
HYP_D2: U2.62 U10.C4
HYP_D3: U2.66 U10.D4
HYP_D4: U2.56 U10.D5
HYP_D5: U2.59 U10.E3
HYP_D6: U2.63 U10.E2
HYP_D7: U2.67 U10.E1
HYP_RESET: U2.103 U10.A4
HYP_RWDS: U2.68 U10.C3
IAN: C30.2(N2) R36.2(N2) TP43.1(N1) U1.8
IAP: C29.1 R35.2(N2) TP45.1(N1) U1.7
IBN: C20.2(N2) R8.2(N2) TP25.1(N1) U1.10
IBP: C19.1 R7.2(N2) TP26.1(N1) U1.9
ICN: C25.2(N2) R17.2(N2) TP29.1(N1) U1.12
ICP: C24.1 R16.2(N2) TP30.1(N1) U1.11
INN: C32.2(N2) R26.2(N2) TP39.1(N1) U1.14
INP: C31.1 R25.2(N2) TP41.1(N1) U1.13
INT: P2.34 U2.127
IRQ0_ADC: U2.112 U4.4
IRQ0_ADE: LED1.C TP10.1(N1) U1.31 U4.25
IRQ1_ADC: U2.6 U4.5
IRQ1_ADE: LED6.C TP8.1(N1) U1.32 U4.24
LCD_A0: P2.10 U2.95
LCD_CSB: P2.14 U2.135
LCD_RST: P2.12 U2.97
LED_0: P2.17 U2.91
LED_1: P2.19 U2.96
LINK_ST: P2.40 U2.139
MISO_ADC: U2.117 U5.5
MISO_ADE: R96.1 TP3.1(N1) U1.38 U5.16
MOSI_ADC: U2.118 U5.4
MOSI_ADE: TP2.1(N1) U1.39 U5.17
NR_D_485: P2.5 U2.144
PM1_ADE: R81.2(N2) TP49.1(N1) U1.5
PPS_RTC: R59.2(N2) R60.2(N2) R62.2(N2) U2.140
REF: FB1.2(N2) U1.16
RESET_ADC: U2.116 U5.7
RESET_ADE: C39.1 R43.1 TP6.1(N1) U1.6 U5.14
RSTN: C180.2(N2) P1.10(N5) R125.2(N2) S1.1 U2.114
RTC_32K: R58.2(N2) U2.107
RTC_SCL: R57.2(N2) U2.20 U3.8
RTC_SDA: R61.2(N2) U2.19 U3.7
RXD_485: P2.1 U2.143
RXEV: P2.54 U2.40
SCL_0: P2.21 R53.2(N2) U2.130
SCLK_ADC: U2.115 U5.3
SCLK_ADE: TP1.1(N1) U1.37 U5.18
SDA_0: P2.23 R55.2(N2) U2.129
SDIO_CD: P2.51 U2.61
SDIO_CLK: P2.53 U2.51
SDIO_CMD: P2.55 U2.37
SDIO_DAT0: P2.43 U2.45
SDIO_DAT1: P2.45 U2.49
SDIO_DAT2: P2.47 U2.39
SDIO_DAT3: P2.49 U2.43
SHIELD: P10.GND1 P10.GND2
SPI0_MISO: P2.16 U2.138
SPI0_MOSI: P2.6 U2.141
SPI0_SCK: P2.8 U2.142
SPI0_SS0: P2.18(N9) U2.10
SPI2_MISO__SPI_CFG1: P2.32 U2.123
SPI2_MOSI: P2.30 U2.124
SPI2_SCK: P2.28 U2.122
SPI2_SS0: P2.26 U2.125
SPI3_MISO: P2.29 U2.35
SPI3_MOSI: P2.31 U2.36
SPI3_SCK: P2.25 U2.30
SPI3_SDIO2: P2.50 U2.31
SPI3_SDIO3: P2.48 U2.28
SPI3_SS0: P2.52 U2.34
SPI3_SS1: P2.44 U2.25
SPI3_SS2: P2.46 U2.26
SPI3_SS3: P2.27 U2.32
SPI_CFG1: P2.36 U2.120
SPIXF_SCK: U2.13 U11.6
SPIXF_SDIO0: U2.17 U11.5
SPIXF_SDIO1: U2.15 U11.2
SPIXF_SDIO2: U2.22 U11.3(WP_N/SIO2)
SPIXF_SDIO3: U2.23 U11.7
SPIXF_SS0: U2.12 U11.1
SPIXR_SCK: P2.2 U2.4
SPIXR_SDIO0: P2.4 U2.2
SPIXR_SDIO1: P2.58 U2.7
SS_ADC: U2.70 U5.6
SS_ADE: R54.1 TP4.1(N1) U1.40 U5.15
SWPD_EN: P2.20 U2.133
TCK: P1.4 U2.110
TMS: P1.2 U2.113
TS_CAPT: P2.42 U2.16
TS_TIMER__MS_SEL: P2.38 U2.131
TX2P4_EN: P2.22 U2.134
TXD_485: P2.3 U2.1
TXEV: P2.56 U2.41
UART0_RX: P1.8 U2.132
UART0_TX: P1.6 U2.137
UART2_CTS: P2.33 U2.38
UART2_PPS: P2.41 U2.8
UART2_RTS: P2.35 U2.46
UART2_RX: P2.37 U2.48
UART2_TX: P2.39 U2.50
UC_LED0: R78.1 U2.57
UC_LED1: R79.1 U2.44
UNNAMED_4_ADMAX31343_I226_CLKO: R58.1 U3.1
UNNAMED_4_ADMAX31343_I226_INTN: R60.1 U3.3
UNNAMED_4_ADMAX31343_I226_SQW: R59.1 U3.4
UNNAMED_4_ADMAX31343_I226_VBAT: R56.1 U3.6
UNNAMED_4_CAP_I166_N1: C180.1 R126.1
UNNAMED_4_DIOLED_I251_P: DS1.A(P) R77.2(N2)
UNNAMED_4_DIOLED_I254_P: DS2.A(P) R78.2(N2)
UNNAMED_4_DIOLED_I257_P: DS3.A(P) R79.2(N2)
UNNAMED_6_CAP_I27_N2: C41.2(N2) C45.2(N2) FB1.1
UNNAMED_6_DIOLED_I2_P: LED1.A(P) R44.1
UNNAMED_6_DIOLED_I4_P: LED6.A(P) R45.1
UNNAMED_6_DIOLED_I9_P: LED2.A(P) R46.1
UNNAMED_6_DIOLED_I12_P: LED3.A(P) R47.1
UNNAMED_6_DIOLED_I34_P: LED5.A(P) R50.1
UNNAMED_7_CAP_I17_N2: C28.2(N2) R24.2(S2) R26.1
UNNAMED_7_CAP_I20_N1: C26.1 R23.2(S2) R25.1
UNNAMED_7_CAP_I23_N2: C22.2(N2) R15.2(S2) R17.1
UNNAMED_7_CAP_I32_N1: C21.1 R14.2(S2) R16.1
UNNAMED_7_CAP_I38_N2: C18.2(N2) R6.2(S2) R8.1
UNNAMED_7_CAP_I40_N1: C17.1 R5.2(S2) R7.1
UNNAMED_7_CAP_I57_N2: C16.2(N2) R22.2(S2) R36.1
UNNAMED_7_CAP_I58_N1: C15.1 R21.2(S2) R35.1
UNNAMED_7_CN2P_I113_N1: P3.1 Q1.1(P) Q2.2 R1.1 R21.1
UNNAMED_7_CN2P_I113_N2: P3.2(N2) Q1.2 Q2.1(P) R2.2(N2) R22.1
UNNAMED_7_CN2P_I114_N1: P4.1 Q3.1(P) Q4.2 R3.1 R5.1
UNNAMED_7_CN2P_I114_N2: P4.2(N2) Q3.2 Q4.1(P) R4.2(N2) R6.1
UNNAMED_7_CN2P_I115_N1: P5.1 Q5.1(P) Q6.2 R10.1 R14.1
UNNAMED_7_CN2P_I115_N2: P5.2(N2) Q5.2 Q6.1(P) R11.2(N2) R15.1
UNNAMED_7_CN2P_I116_N1: P6.1 Q7.1(P) Q9.2 R19.1 R23.1
UNNAMED_7_CN2P_I116_N2: P6.2(N2) Q7.2 Q9.1(P) R20.2(N2) R24.1
UNNAMED_7_CN4PABC_I117_N1: L1.1 P8.1A
UNNAMED_7_CN4PABC_I117_N2: L2.1 P8.2A
UNNAMED_7_CN4PABC_I117_N3: L3.1 P8.3A
UNNAMED_7_CN4PABC_I117_N4: L4.1 P8.4A
UNNAMED_7_FERRITE_I70_N2: L3.2(N2) R13.1
UNNAMED_7_FERRITE_I72_N2: L2.2(N2) R12.1
UNNAMED_7_FERRITE_I89_N2: L1.2(N2) R9.1
UNNAMED_7_RES_I119_N2: R9.2(N2) R18.1
UNNAMED_7_RES_I120_N2: R18.2(N2) R30.1
UNNAMED_7_RES_I121_N2: R30.2(N2) R37.1
UNNAMED_7_RES_I123_N2: R12.2(N2) R27.1
UNNAMED_7_RES_I124_N2: R27.2(N2) R31.1
UNNAMED_7_RES_I125_N2: R31.2(N2) R38.1
UNNAMED_7_RES_I127_N2: R13.2(N2) R28.1
UNNAMED_7_RES_I128_N2: R28.2(N2) R34.1
UNNAMED_7_RES_I129_N2: R34.2(N2) R39.1
UNNAMED_8_ADLTC3306_I30_PGOOD: R64.2(N2) TP12.1(N1) U6.A1
UNNAMED_8_ADLTC3306_I30_SW: L5.1 U6.B2
UNNAMED_8_CAP_I52_N1: C11.1 R75.2(N2) R76.2(N2)
UNNAMED_8_CN2P_I1_N1: M1.3 P7.1
UNNAMED_8_CN2P_I1_N2: M1.1 P7.2(N2)
UNNAMED_8_RES_I8_N2: R51.2(N2) R52.1 U17.4
UNNAMED_8_RES_I23_N1: R48.2(N2) R49.1 U17.8
UNNAMED_8_RES_I37_N2: Q8.1 R63.2(N2)
UNNAMED_8_RES_I44_N1: R67.2(N2) R68.2(N2) R69.1
UNNAMED_8_RES_I44_N2: C11.2(N2) R69.2(N2) R70.1 R73.2(N2) R74.1 U6.C1(VOUT)
UNNAMED_8_RES_I50_N1: R71.2(N2) R72.2(N2) R73.1
UNNAMED_9_CN16PAB4GND_I20_N3: P10.A5 R157.2(N2)
USB_BUCK_EN: Q8.3 R65.2(N2) R66.1 TP17.1(N1) U6.B1 U9.3 U12.3
USB_DN: L7.4(N4) U2.83
USB_DN_CM: D7.C L7.3 P10.A7
USB_DP: L7.1 U2.78
USB_DP_CM: D6.C L7.2 P10.A6
VAN: C27.1 C52.2(N2) R33.1 TP58.1(N1) U1.19
VAP: C23.1 C52.1 R29.1 R37.2(N2) TP57.1(N1) U1.20
VBN: C35.1 C54.2(N2) R41.1 TP56.1(N1) U1.21
VBP: C33.1 C54.1 R32.1 R38.2(N2) TP55.1(N1) U1.22
VCN: C36.1 C55.2(N2) R42.1 TP54.1(N1) U1.23
VCP: C34.1 C55.1 R39.2(N2) R40.1 TP53.1(N1) U1.24
VPWR_USB: C8.P C9.1 D10.C P10.A4 P10.A9 R64.1 R65.1 TP11.1(N1) U6.C2
XIN_ADE: C38.1 U1.29 X2.1
XOUT_ADE: C37.1 U1.30 X2.3(IN/OUT2)

Pads without a net: M1 13; P1 7; P8 1B 1C 2B 2C 3B 3C 4B 4C; P10 A8 B1 B4 B5 B6 B7 B8 B9 B12 GND3 GND4; U2 3 42 73 74 75 77 79 82 84 86 87 101 102 104 105 106 108 109; U4 13 16; U7 4; U8 4; U9 4; U10 A2 A5 B5 C2 C5; U12 4

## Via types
v1: diameter 0.508, hole 0.254, TOP to BOTTOM, 799 vias

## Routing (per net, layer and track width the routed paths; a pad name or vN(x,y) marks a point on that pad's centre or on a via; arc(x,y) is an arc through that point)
1V1: length 78.9
  TOP w0.254: 26.69,86.74 U2.88 ; v1(50.84,78.37) 50.47,78.74 U2.5 ; U2.14 v1(48.12,83.24)
  TOP w0.305: 26.69,86.74 24.89,86.74 C79.1 ; C125.1 76.56,100.78 75.98,100.2 U17.7 ; R48.1 77.1,103.51 v1(77.13,103.49) ; C80.1 51.91,78.37 v1(50.84,78.37)
  TOP w0.508: C79.1 C78.1 v1(24.87,88.39)
  L3_PWR w0.762: 46.14,105.11 33.98,105.11 27.52,98.66 21.96,98.66 17.06,93.76 17.06,90.05 16.04,89.04 6.7,89.04 5.63,87.97 5.63,72.91 TP15.1
  vias: v1(77.66,100.8)
1V8: length 102.5
  TOP w0.152: C63.2 v1(26.58,96.53)
  TOP w0.254: U2.111 30.86,73.57 30.77,73.49 ; U10.E4 57.97,98.18 v1(58.08,98.18) ; U2.33 v1(51.88,92.74) ; U10.B4 v1(58.05,100.23) ; U2.99 26.56,81.24 ; U2.55 v1(38.36,97.8) ; v1(54.02,99.2) 54.08,99.2 U10.D1 ; U2.21 50.52,86.74 50.56,86.7 51.73,86.7 v1(51.78,86.75) ; U2.126 v1(38.36,75.98)
  TOP w0.279: P2.60 59.74,68.37 60.1,68.73
  TOP w0.305: 30.86,71.32 C82.1 C83.1 ; 30.86,71.32 v1(30.17,71.32) ; 30.86,71.32 30.77,71.41 30.77,73.49 ; C88.2 C89.2 v1(62.44,100.38) ; C96.1 55.26,90.1 v1(54.73,90.1) ; C62.2 38.36,99.09 v1(38.36,97.8) ; 26.56,81.24 26.13,81.67 C64.2 C68.2 v1(25,79.66) ; C86.1 C87.1 61.06,97.09 61.64,97.67 v1(61.64,98.18) ; C84.2 C85.1 53,98.18 v1(54.02,99.2) ; C142.1 v1(28.74,73.03)
  TOP w0.483: 52.3,92.74 C65.2 ; 52.3,92.74 52.29,92.74 v1(51.88,92.74) ; 52.3,92.74 C69.2 ; C66.2 C62.2 ; C67.2 v1(51.78,86.75)
  TOP w0.508: v1(55.24,88.71) U11.8 ; 75.6,97.8 C124.1 ; 75.6,97.8 v1(76.37,97.8) ; 75.6,97.8 R51.1 ; v1(18.1,87.82) C101.1 16.93,89.09 P1.1
  TOP w0.635: 60.1,68.73 60.54,69.17 v1(60.54,70.34) v1(60.54,71.1)
  L3_PWR w1.016: 55.23,87.41 59.3,87.41 60.54,86.17 v1(60.54,71.1) v1(60.54,70.34)
  BOTTOM w0.762: 17.82,87.13 7.71,87.13 6.7,86.11 6.7,83.14 10.18,79.66 10.18,72.88 5.25,67.95 TP13.1
  vias: v1(46.19,88.65) v1(46.19,87.38) v1(47.46,88.65) v1(47.46,87.38)
3V3: length 68
  TOP w0.254: U2.54 38.86,97.29 38.95,97.39 38.95,98.61 v1(39.28,98.94) ; U2.9 50.36,80.74 50.43,80.81 51.32,80.81 ; U2.128 39.36,73.54 v1(39.23,73.41) 39.23,72.01 C81.1 ; U2.76 v1(25.79,92.74) ; U2.18 52.3,85.24
  TOP w0.279: v1(60.21,59.44) 59.74,59.92 P2.59 P2.57 v1(59.24,59.44) ; 71.5,100.2 71.26,100.44 71.53,100.7 U17.1 U17.2 71.5,100.2
  TOP w0.305: R57.1 v1(12.49,77.1) ; 51.32,80.81 51.86,80.27 C77.1 ; C75.1 C70.1 25.77,92.72 v1(25.79,92.74) ; v1(39.33,64.14) 39.53,64.34 R53.1 ; v1(9.95,87.97) R125.1 ; R71.1 v1(84.75,102.68) ; R61.1 v1(14.01,77.1) ; R75.1 v1(88.56,102.68) ; R55.1 v1(64.43,59.06) ; R67.1 v1(80.94,102.88) ; v1(76.57,99.7) U17.6 ; R77.1 v1(8.09,80.53)
  TOP w0.33: U3.2 v1(13.56,68.41)
  TOP w0.432: U4.11 v1(48.06,56) ; U4.1 v1(54.56,55.98)
  TOP w0.483: C76.1 C73.1 42.77,99.76 v1(42.84,99.83)
  TOP w0.508: 15.66,60.44 15.66,62.48 C4.2 v1(15.93,65.52) ; C3.1 58.39,55.9 C2.2 57.06,55.98 v1(54.56,55.98) ; 71.26,100.44 v1(71.26,99.02) v1(71.26,98.31) ; C123.1 77.22,99.7 v1(76.57,99.7) ; C71.1 C74.1 52.3,83.98 v1(52.3,83.98) v1(52.3,81.95) 52.3,81.29 C72.1 C77.1 ; v1(91.35,96.17) U12.5 ; U9.5 v1(93.16,102.78) ; U7.5 v1(76.81,95.07) ; U8.5 v1(69.7,95.07) ; R62.1 v1(16.8,68.46) ; C1.2 v1(10.96,69.35)
3V3_USB: length 93.1
  TOP w0.305: v1(96.05,100.72) 96.05,99.96 96.94,99.07 C12.1 97.2,99.07 98.08,99.96 v1(98.08,100.72) ; R68.1 v1(82.84,103.67) ; U9.1 v1(92.44,98.81) ; v1(72.3,69.35) 72.3,70.11 71.75,70.67 L5.2 69.56,70.67 69,70.11 v1(69,69.35) ; U12.1 v1(91.72,93.83) ; R72.1 v1(86.65,103.67) ; R76.1 v1(90.34,103.69)
  L3_PWR w0.762: 71.11,55.23 70.14,54.26 47.28,54.26 46.52,55.03 46.52,57.11 43.6,60.03 33.64,60.03 29.45,64.22 14.62,64.22 8.27,70.57 8.27,73.57 TP18.1
3V3_WALL: length 23
  TOP w0.406: 74.21,89.85 C10.1 ; C10.1 75.5,90.94 ; C10.1 72.91,90.94 ; 71.15,88.93 R63.1 71.76,88.27 ; 71.6,90.11 U8.3 72.15,91.17 ; 76.81,90.11 U7.1 76.27,91.17
  TOP w0.508: 70.53,89.37 69.7,90.19 U8.1 ; U7.3 78.71,90.11
  TOP w1.016: M1.16 77.74,80.02 76.65,81.11 76.65,88.22
+3V3_ADE: length 23.2
  TOP w0.305: U1.27 v1(34.6,46.82) ; U1.1 33.1,39.41 v1(32.43,38.74) ; R43.2 v1(31.03,38.24)
  TOP w0.406: U4.18 v1(48.06,41.64) ; v1(55.03,41.66) 55.03,43.16 54.56,43.64 U4.28
  TOP w0.508: v1(27.73,46.03) 27.73,44.95 C40.2 ; v1(32.41,46.26) 31,46.26 C44.2 ; R96.2 v1(29.25,46.11) ; R50.2 v1(9.57,40.27) ; R45.2 v1(9.57,41.92) ; C7.1 v1(50.84,39.76) ; v1(16.93,48.52) C6.2 15.66,48.79 15.66,50.82 ; R44.2 v1(9.57,43.57) ; R54.2 v1(29.25,39.18) ; C5.2 v1(49.21,39.89)
AVDDOUT: length 4.4
  TOP w0.254: U1.25 35.6,48.07 35.92,48.4 C46.2 35.92,50.32 C42.2
DGND: length 190.2
  TOP w0.152: U10.E5 v1(58.97,98.18) ; U2.119 v1(34.86,75.97) ; 14.13,61.73 v1(14.13,61.63) ; D7.A v1(13.03,96.18) ; v1(54.02,100.21) 54.07,100.21 U10.C1 ; v1(29.12,90.94) 28.92,90.74 U2.80 ; U2.81 28.94,90.24 v1(29.12,90.05) ; D6.A v1(13.03,99.42) ; U2.11 v1(48.13,81.74) ; 72.3,99.7 U17.3 ; U6.A2 v1(69.89,75.45) ; U2.136 v1(43.36,73.22) ; U10.B3 56.53,100.74 v1(56.05,101.23)
  TOP w0.254: U2.60 v1(35.86,95) ; U2.98 v1(29.08,81.74)
  TOP w0.406: 3.98,63.34 TP14.1 ; TP14.1 2.92,64.4 ; TP14.1 3.98,65.45 ; TP14.1 5.03,64.4 ; R74.2 84.75,93.95 ; R74.2 84.75,92.58 ; R74.2 83.96,93.27 ; R74.2 85.54,93.27 ; TP16.1 20.65,62.75 ; TP16.1 19.6,63.8 ; TP16.1 18.54,62.75 ; TP16.1 19.6,61.69 ; 24.1,80.08 C68.1 ; C68.1 C64.1 v1(23.41,81.67) ; C68.1 v1(23.41,80.65) ; D10.A 9.02,104.75 ; D10.A 8.32,104.15 ; D10.A 9.72,104.15 ; D10.A 9.02,103.55 ; 11.19,88.65 P1.9 ; P1.9 11.85,90.34 ; P1.9 11.85,86.97 ; 50.24,99.2 C84.1 ; C84.1 C85.2 ; C84.1 50.77,99.77 ; 23.97,92.15 C70.2 23.44,92.72 ; C67.1 53.2,87.32 ; C67.1 v1(53.89,86.75) ; C67.1 C71.2 ; DS1.C 4.46,82.99 ; DS1.C 4.46,81.62 ; DS1.C 5.15,82.3 ; DS1.C 3.77,82.3 ; 61.19,53.91 C3.2 ; C3.2 61.19,56.09 ; C3.2 62.13,55 ; 24.99,95.96 C63.1 ; C63.1 24.99,97.1 ; C63.1 24.46,96.53 ; 23.14,72.89 BT1.N ; BT1.N 22.47,74.4 ; BT1.N 23.14,75.92 ; 77.23,98.26 C123.2 77.8,98.8 ; 72.44,95.87 R52.2 ; R52.2 71.83,96.53 ; R52.2 72.44,97.19 ; 53.2,84.15 C74.2 ; C74.2 C71.2 ; C74.2 53.73,84.72 ; C78.2 23.97,88.31 ; C78.2 C79.2 ; C78.2 23.44,87.74 ; 72.91,93.73 74.21,93.73 ; 74.21,93.73 74.21,92.64 ; 74.21,93.73 74.21,94.83 ; 74.21,93.73 75.5,93.73 ; C71.2 v1(53.89,85.73) ; C80.2 53.2,79.32 ; C80.2 53.2,78.18 ; C80.2 53.73,78.75 ; C77.2 53.73,80.27 ; C77.2 53.2,79.7 ; C77.2 C72.2 ; 63.97,98.66 C88.1 ; C88.1 C89.1 ; C88.1 64.51,99.23 ; 72.72,103.51 R49.2 ; R49.2 73.33,104.17 ; R49.2 73.33,102.85 ; 4.46,88.73 DS3.C ; DS3.C 4.46,90.1 ; DS3.C 5.15,89.42 ; DS3.C 3.77,89.42 ; 30.33,70.42 C82.2 C83.2 32.49,70.42 ; C81.2 39.98,70.93 ; C81.2 39.41,70.4 ; C81.2 38.84,70.93 ; C96.2 56.33,90.5 ; C96.2 56.33,89.36 ; C96.2 56.86,89.93 ; 69.01,81.77 R66.2 ; R66.2 69.01,83.09 ; R66.2 68.4,82.43 ; v1(42.84,100.59) 42.77,100.66 C73.2 C76.2 C66.1 C62.1 38.34,100.66 v1(38.27,100.59) ; 26.62,73.03 C142.2 ; C142.2 27.15,73.61 ; C142.2 27.15,72.46 ; C79.2 23.44,86.72 ; C79.2 23.97,86.15 ; C89.1 64.51,100.38 ; C89.1 63.97,100.95 ; 15.73,80.59 R126.2 16.26,81.16 ; S1.2 16.77,79 ; S1.2 16.09,77.86 ; S1.2 16.09,80.15 ; S1.2 15.4,79 ; 50.24,98.18 C85.2 ; C85.2 50.77,97.61 ; 53.2,91.64 C65.1 ; C65.1 C69.1 ; C65.1 53.73,92.21 ; 14.13,61.73 C4.1 ; C4.1 13.26,62.75 ; C4.1 14.13,63.76 ; Q8.2 69.54,85.21 ; Q8.2 69.54,83.61 ; Q8.2 70.53,84.41 ; Q8.2 68.54,84.41 ; 93.39,92.78 U12.2 93.39,94.89 ; 23.44,93.73 C75.2 23.97,94.31 ; U11.4 59.05,81.33 ; U11.4 59.65,80.24 ; U11.4 59.05,79.15 ; 10.96,64.92 C1.1 ; C1.1 11.98,65.78 ; C1.1 9.95,65.78 ; R157.1 11.24,102.36 ; R157.1 10.58,102.97 ; R157.1 9.92,102.36 ; 68.76,54.28 C8.N ; C8.N v1(67.2,55.84) ; C8.N 70.16,55.84 ; C8.N 68.76,57.4 ; C69.1 53.73,93.23 ; C69.1 53.2,93.8 ; 93.39,101.49 U9.2 93.39,99.38 ; 57.14,53.24 C2.1 ; C2.1 56.12,54.1 ; C2.1 58.16,54.1 ; M1.14 81.68,85.1 ; M1.14 80.69,84.11 ; M1.14 79.69,85.1 ; M1.14 80.69,86.09 ; 80.94,94.78 R70.2 ; R70.2 80.28,95.39 ; R70.2 81.6,95.39 ; 97.07,95.18 C12.2 ; C12.2 97.07,97.37 ; C12.2 98.36,96.27 ; C12.2 95.77,96.27 ; DS2.C 4.46,86.55 ; DS2.C 4.46,85.17 ; DS2.C 5.15,85.86 ; DS2.C 3.77,85.86 ; C72.2 53.73,81.29 ; C72.2 53.2,81.86 ; P1.3 15.66,90.34 ; 18.67,89.99 C101.2 18.1,90.53 ; P1.5 14.39,90.34 ; 69.09,81.03 C9.2
  TOP w0.432: v1(42.71,64.14) P2.PAD1 45.99,64.14 ; P2.PAD2 v1(46.52,64.14) ; v1(62.27,64.14) P2.PAD4 v1(58.46,64.14) P2.PAD3
  TOP w0.508: v1(77.76,92.39) U7.2 ; U8.2 v1(70.65,92.39)
  L2_GND w0.305: P10.A1 8.8,100.85 ; P10.A12 8.78,94.9
  L2_GND w0.635: M1.14 81.51,85.92 ; M1.14 81.51,84.27 ; M1.14 79.86,84.27 ; M1.14 79.86,85.92 ; 18.73,61.88 TP16.1 ; TP16.1 20.47,61.88 ; TP16.1 20.47,63.62 ; TP16.1 18.73,63.62 ; 3.11,63.53 TP14.1 ; TP14.1 4.85,65.27 ; TP14.1 3.11,65.27 ; TP14.1 4.85,63.53
  BOTTOM w0.406: M1.14 81.68,85.1 ; M1.14 79.69,85.1 ; M1.14 80.69,86.09 ; M1.14 80.69,84.11 ; TP14.1 3.98,65.45 ; TP14.1 5.03,64.4 ; TP14.1 3.98,63.34 ; 19.6,61.69 TP16.1 ; TP16.1 18.54,62.75 ; TP16.1 20.65,62.75
  vias: v1(1.31,91.12) v1(1.34,61.55) v1(2.17,104.43) v1(3.47,60.08) v1(3.6,89.42) v1(3.6,85.86) v1(3.6,82.28) v1(3.88,79.28) v1(4.28,66.25) v1(6.24,66.81) v1(6.21,63.64) v1(8.52,85.84) v1(9.85,65.79) v1(9.9,104.15) v1(10.56,103.16) v1(10.58,94.01) v1(10.96,64.76) v1(11.85,90.51) v1(13.25,71.79) v1(13.25,70.52) v1(13.88,71.13) v1(14.39,104.4) v1(14.52,71.79) v1(14.52,70.52) v1(14.77,90.51) v1(14.86,73.92) v1(15.69,90.51) v1(16.55,101.63) v1(16.55,81.16) v1(16.73,59.67) v1(17.31,79.89) v1(17.31,78.11) v1(17.54,62.75) v1(18.05,65.85) v1(18.1,90.71) v1(19.24,73.29) v1(19.42,69.17) v1(20.23,82.3) v1(20.23,78.11) v1(20.74,103.51) v1(20.74,100.54) v1(22.09,105.09) v1(22.19,65.85) v1(22.19,62.8) v1(22.37,59.69) v1(22.6,94.95) v1(23.14,76.07) v1(23.15,72.7) v1(23.26,87.74) v1(23.26,86.72) v1(23.28,93.73) v1(23.28,92.72) v1(24.02,70.24) v1(24.3,96.53) v1(24.78,68.13) v1(25.49,62.8) v1(26.02,65.85) v1(26.46,73.03) v1(26.63,88.25) v1(28.41,104.28) v1(28.41,100.87) v1(29.12,86.24) v1(30.17,70.44) v1(31.36,59.8) v1(32.53,63.81) v1(32.88,70.42) v1(33.26,92.49) v1(33.31,86.9) v1(33.29,80.6) v1(33.67,65.36) v1(36.87,89.65) v1(36.95,83.09) v1(38.5,63.76) v1(38.67,71.1) v1(40.27,92.41) v1(40.33,86.93) v1(40.3,81.29) v1(40.3,76.62) v1(42.18,57.79) v1(42.36,95.13) v1(42.41,78.09) v1(44.62,68.97) v1(45.43,55.18) v1(45.43,53.86) v1(46.8,76.62) v1(47.39,55.56) v1(48.25,90.75) v1(48.25,89.75) v1(48.73,55.48) v1(49.39,55.48) v1(50.05,55.48) v1(50.84,100.21) v1(50.76,97.44) v1(53.2,91.47) v1(53.58,55.41) v1(53.89,92.8) v1(53.89,85.02) v1(53.89,81.29) v1(53.89,80.27) v1(53.89,78.75) v1(55.95,53.4) v1(56.56,85.86) v1(57.04,90.1) v1(58.31,53.4) v1(59.05,78.63) v1(59.07,81.52) v1(61.18,56.24) v1(61.81,69.73) v1(62.28,95.26) v1(62.32,55.23) v1(62.4,98.18) v1(63.11,101.23) v1(64.67,100.21) v1(64.67,99.41) v1(68.04,84.41) v1(68.11,82.43) v1(68.19,105.52) v1(68.62,81.03) v1(68.85,61.38) v1(68.82,57.49) v1(69.2,67.55) v1(70.32,55.81) v1(71.67,96.53) v1(71.97,99.37) v1(72.05,67.55) v1(72.74,93.73) v1(73.12,97.39) v1(73.35,104.35) v1(73.47,95) v1(74.11,100.52) v1(74.11,99.95) v1(74.11,99.37) v1(75.68,102.12) v1(75.68,93.73) v1(76.72,76.31) v1(77.1,71.03) v1(77.23,98.1) v1(78.27,58.02) v1(78.86,103.03) v1(78.91,100.39) v1(78.86,96.88) v1(79.8,102.12) v1(79.8,97.8) v1(79.95,62.14) v1(80,68.08) v1(80.08,65.16) v1(80.94,94.5) v1(81.19,91.63) v1(82.11,55.74) v1(82.18,73.31) v1(83.58,63) v1(84.06,68.67) v1(84.75,92.21) v1(84.72,58.3) v1(85.08,86.8) v1(85.64,77.66) v1(93.39,101.66) v1(93.39,98.81) v1(93.39,92.59) v1(95.61,96.27) v1(96.84,103.26) v1(97.09,95) v1(98.53,96.3) v1(101.39,102.32) v1(101.92,93.25)
